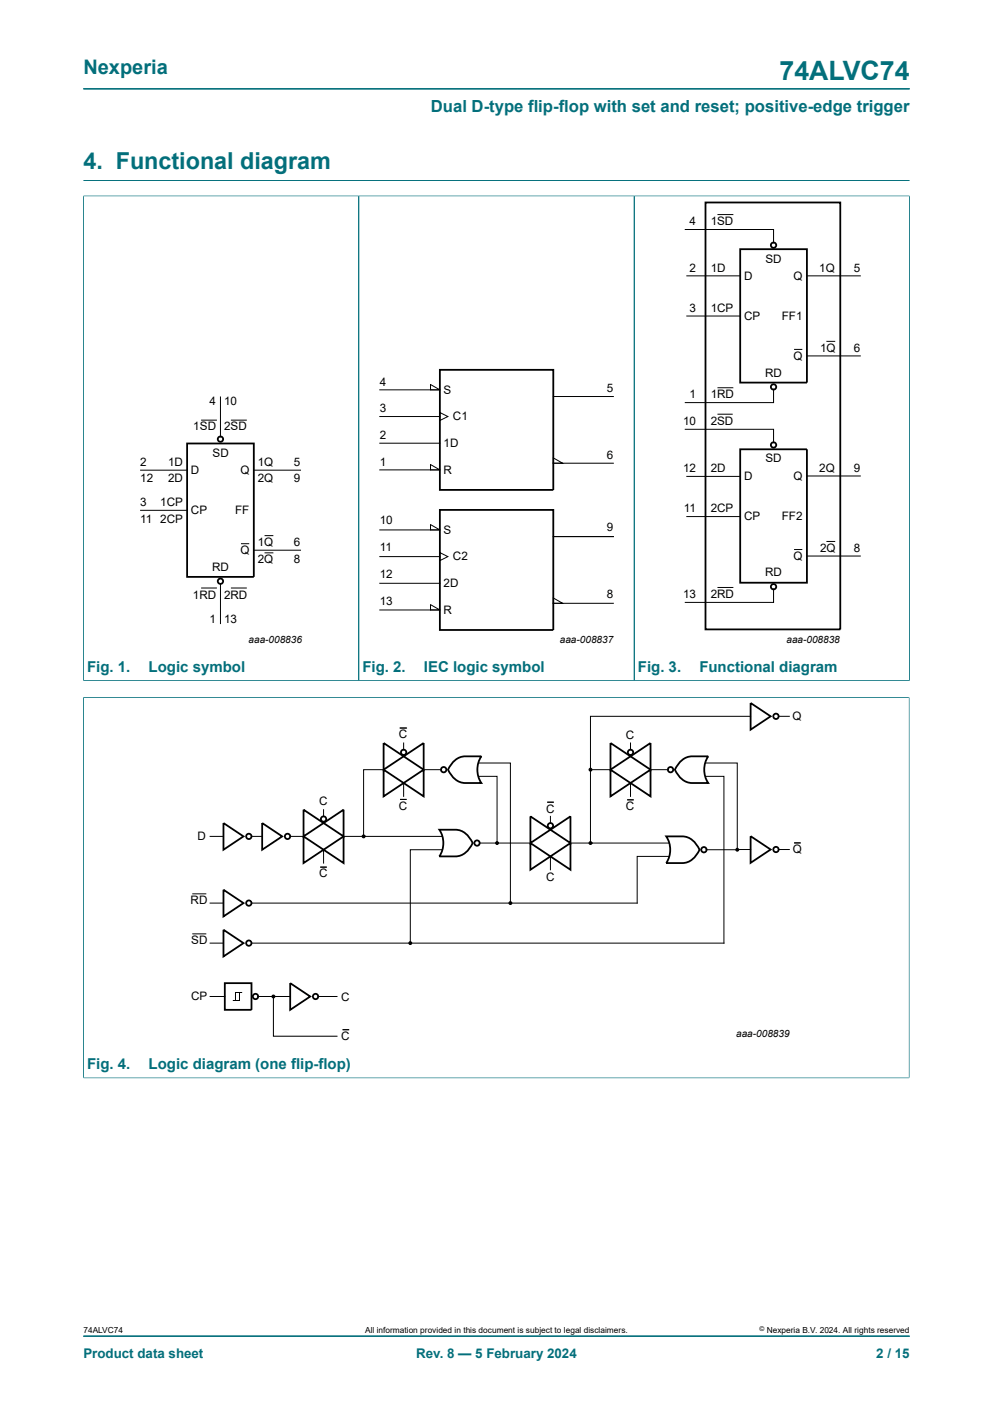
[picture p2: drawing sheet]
<svg xmlns="http://www.w3.org/2000/svg" width="210mm" height="297mm" viewBox="0 0 210 297" stroke-linecap="round" stroke-linejoin="round" font-family="sans-serif">
<defs><g id="words">
<text font-size="5.6" fill="#036f7b" x="164.9" y="16.8">74ALVC74</text>
<text font-size="4.9" fill="#036f7b" x="17.6" y="35.9">4. Functional diagram</text>
<text font-size="4.2" fill="#036f7b" x="17.6" y="15.6">Nexperia</text>
<text font-size="3.5" fill="#036f7b" x="91.1" y="23.7">Dual D-type flip-flop with set and reset; positive-edge trigger</text>
<g font-size="3.2" fill="#036f7b">
<text x="18.4" y="142.1">Fig. 1.</text>
<text x="31.4" y="142.1">Logic symbol</text>
<text x="76.7" y="142.1">Fig. 2.</text>
<text x="89.7" y="142.1">IEC logic symbol</text>
<text x="134.9" y="142.1">Fig. 3.</text>
<text x="147.9" y="142.1">Functional diagram</text>
<text x="18.4" y="226.2">Fig. 4.</text>
<text x="31.4" y="226.2">Logic diagram (one flip-flop)</text>
</g>
<g font-size="2.8" fill="#036f7b">
<text x="17.6" y="287.2">Product data sheet</text>
<text x="88" y="287.2">Rev. 8 — 5 February 2024</text>
<text x="185.3" y="287.2">2 / 15</text>
</g>
<g font-size="2.5">
<text x="145.8" y="47.6">4</text>
<text x="150.3" y="47.6">1SD</text>
<text x="145.8" y="57.5">2</text>
<text x="150.3" y="57.5">1D</text>
<text x="157.4" y="59.2">D</text>
<text x="161.9" y="55.6">SD</text>
<text x="167.8" y="59.2">Q</text>
<text x="173.2" y="57.5">1Q</text>
<text x="180.5" y="57.5">5</text>
<text x="145.8" y="66">3</text>
<text x="150.3" y="66">1CP</text>
<text x="157.4" y="67.6">CP</text>
<text x="165.4" y="67.6">FF1</text>
<text x="167.8" y="76.1">Q</text>
<text x="173.4" y="74.4">1Q</text>
<text x="180.5" y="74.4">6</text>
<text x="80.3" y="81.6">4</text>
<text x="93.8" y="83.3">S</text>
<text x="128.3" y="83">5</text>
<text x="161.8" y="79.7">RD</text>
<text x="44.3" y="85.7">4</text>
<text x="47.4" y="85.7">10</text>
<text x="80.3" y="87.2">3</text>
<text x="95.8" y="88.9">C1</text>
<text x="144.5" y="90">10</text>
<text x="145.8" y="84.3">1</text>
<text x="150.3" y="84.3">1RD</text>
<text x="150.3" y="89.8">2SD</text>
<text x="40.9" y="91.1">1SD</text>
<text x="47.4" y="91.1">2SD</text>
<text x="80.3" y="92.9">2</text>
<text x="93.8" y="94.5">1D</text>
<text x="29.6" y="98.5">2</text>
<text x="35.6" y="98.5">1D</text>
<text x="40.4" y="100.3">D</text>
<text x="44.9" y="96.7">SD</text>
<text x="50.9" y="100.3">Q</text>
<text x="54.5" y="98.5">1Q</text>
<text x="62.2" y="98.5">5</text>
<text x="80.3" y="98.5">1</text>
<text x="93.8" y="100.2">R</text>
<text x="128.3" y="97.1">6</text>
<text x="144.5" y="99.9">12</text>
<text x="150.3" y="99.9">2D</text>
<text x="157.4" y="101.6">D</text>
<text x="161.9" y="97.7">SD</text>
<text x="167.8" y="101.5">Q</text>
<text x="173.2" y="99.8">2Q</text>
<text x="180.5" y="99.8">9</text>
<text x="29.6" y="102">12</text>
<text x="29.6" y="107.1">3</text>
<text x="33.9" y="107.1">1CP</text>
<text x="35.6" y="102">2D</text>
<text x="54.5" y="102">2Q</text>
<text x="62.2" y="102">9</text>
<text x="29.6" y="110.5">11</text>
<text x="33.9" y="110.5">2CP</text>
<text x="40.4" y="108.7">CP</text>
<text x="49.7" y="108.7">FF</text>
<text x="80.3" y="110.9">10</text>
<text x="93.8" y="112.9">S</text>
<text x="128.3" y="112.3">9</text>
<text x="144.6" y="108.4">11</text>
<text x="150.3" y="108.4">2CP</text>
<text x="157.4" y="110">CP</text>
<text x="165.4" y="110">FF2</text>
<text x="50.9" y="117.2">Q</text>
<text x="54.5" y="115.5">1Q</text>
<text x="54.5" y="119.1">2Q</text>
<text x="62.2" y="115.5">6</text>
<text x="62.2" y="119.1">8</text>
<text x="80.3" y="116.6">11</text>
<text x="95.8" y="118.6">C2</text>
<text x="167.8" y="118.4">Q</text>
<text x="173.4" y="116.8">2Q</text>
<text x="180.5" y="116.8">8</text>
<text x="44.9" y="120.8">RD</text>
<text x="80.3" y="122.2">12</text>
<text x="93.8" y="124.2">2D</text>
<text x="161.8" y="121.8">RD</text>
<text x="40.8" y="126.6">1RD</text>
<text x="44.3" y="131.9">1</text>
<text x="47.4" y="126.6">2RD</text>
<text x="47.4" y="131.9">13</text>
<text x="80.3" y="127.9">13</text>
<text x="93.8" y="129.9">R</text>
<text x="128.3" y="126.5">8</text>
<text x="144.5" y="126.5">13</text>
<text x="150.3" y="126.5">2RD</text>
<text x="167.6" y="152.3">Q</text>
<text x="84.3" y="156.2">C</text>
<text x="132.4" y="156.4">C</text>
<text x="67.5" y="170.4">C</text>
<text x="84.3" y="171.3">C</text>
<text x="115.5" y="171.9">C</text>
<text x="132.4" y="171.4">C</text>
<text x="41.8" y="177.7">D</text>
<text x="67.5" y="185.6">C</text>
<text x="167.7" y="180.5">Q</text>
<text x="40.3" y="191.3">RD</text>
<text x="115.5" y="186.4">C</text>
<text x="40.4" y="199.8">SD</text>
<text x="40.4" y="211.6">CP</text>
<text x="72.2" y="211.6">C</text>
<text x="72.2" y="220">C</text>
</g>
<g font-size="2.1">
<text x="52.6" y="136.1">aaa-008836</text>
<text x="118.4" y="136.1">aaa-008837</text>
<text x="166.3" y="136.1">aaa-008838</text>
<text x="155.7" y="219.4">aaa-008839</text>
</g>
<g font-size="1.8">
<text x="17.6" y="282">74ALVC74</text>
<text x="77.2" y="282">All information provided in this document is subject to legal disclaimers.</text>
<text x="162.2" y="282">Nexperia B.V. 2024. All rights reserved</text>
</g>
<text font-size="1.4" x="160.6" y="281.6">©</text>
</g></defs>
<g fill="none" stroke="#036f7b" stroke-width=".21">
<path d="M17.6 18.8h174.8M17.6 38.2h174.8M17.6 41.5h174.8M17.6 41.4v102.7M75.9 41.5v102.5M134.1 41.5v102.5M192.4 41.4v102.7M17.6 147.5h174.7M17.6 144h174.8M17.6 147.4v80.7M192.3 147.4v80.7M17.6 228h174.7"/>
<path d="M17.6 282.6h174.8"/>
</g>
<g fill="none" stroke="#000" stroke-width=".38">
<path d="M149.2 42.8h28.5v90.3h-28.5zM156.5 52.7h14.1v28.2h-14.1zM93 78.2h24v25.4h-24zM39.6 93.8h14.1v28.2h-14.1zM156.5 95h14.1v28.3h-14.1zM93 107.9h24v25.4h-24zM81.1 157.2l4.3 2.8-4.3 2.8zM85.4 160l4.2-2.8v5.6zM129.1 157.2l4.2 2.8-4.2 2.8zM133.3 160l4.3-2.8v5.6zM158.7 148.7l4.3 2.8-4.3 2.9zM47.3 174.1l4.2 2.8-4.2 2.9z"/>
<path d="M55.4 174.1l4.3 2.8-4.3 2.9zM64.2 171.3l4.2 2.8-4.2 2.8zM64.2 176.9l4.2 2.9-4.2 2.8zM68.4 174.1l4.3-2.8v5.6zM68.4 179.8l4.3-2.9v5.7zM81.1 162.8l4.3 2.8-4.3 2.9zM85.4 165.6l4.2-2.8v5.7zM92.9 175.5h3.4a4.1 4.1 0 0 1 3.7 2.8 4.4 4.4 0 0 1-3.7 2.9h-3.4a5.1 5.1 0 0 0 0-5.7zM96 161a3.4 3.4 0 0 1 2.4-1h3.4a5.1 5.1 0 0 0 0 5.6h-3.4a4.1 4.1 0 0 1-3.7-2.8zM112.2 172.7l4.2 2.8-4.2 2.8zM112.2 178.3l4.2 2.9-4.2 2.8zM116.4 175.5l4.2-2.8v5.6z"/>
<path d="M129.1 162.8l4.2 2.8-4.2 2.9zM133.3 165.6l4.3-2.8v5.7zM140.9 176.9h3.4a4.1 4.1 0 0 1 3.6 2.9 4.4 4.4 0 0 1-3.6 2.8h-3.4a5.1 5.1 0 0 0 0-5.7zM144 161a3.4 3.4 0 0 1 2.4-1h3.4a5.1 5.1 0 0 0 0 5.6h-3.4a4.1 4.1 0 0 1-3.7-2.8zM158.7 176.9l4.3 2.8-4.3 2.8zM47.3 188.2l4.2 2.8-4.2 2.9zM47.3 196.7l4.2 2.8-4.2 2.8zM116.4 181.2l4.2-2.9v5.7zM47.5 208h5.7v5.6h-5.7zM61.4 208l4.2 2.8-4.2 2.8z"/>
<circle cx="163.6" cy="51.9" r=".57"/>
<circle cx="46.6" cy="92.9" r=".56"/>
<circle cx="163.6" cy="81.9" r=".57"/>
<circle cx="163.6" cy="94.1" r=".57"/>
<circle cx="46.6" cy="123" r=".56"/>
<circle cx="163.6" cy="124.1" r=".57"/>
<circle cx="85.4" cy="159.1" r=".56"/>
<circle cx="133.3" cy="159.1" r=".56"/>
<circle cx="164.1" cy="151.5" r=".56"/>
<circle cx="52.6" cy="176.9" r=".56"/>
<circle cx="60.8" cy="176.9" r=".56"/>
<circle cx="68.4" cy="173.3" r=".56"/>
<circle cx="93.8" cy="162.8" r=".56"/>
<circle cx="100.9" cy="178.3" r=".56"/>
<circle cx="116.4" cy="174.7" r=".56"/>
<circle cx="141.8" cy="162.8" r=".56"/>
<circle cx="148.9" cy="179.8" r=".56"/>
<circle cx="164.1" cy="179.7" r=".56"/>
<circle cx="52.6" cy="199.5" r=".56"/>
<circle cx="52.6" cy="191" r=".56"/>
<circle cx="54" cy="210.8" r=".56"/>
<circle cx="66.7" cy="210.8" r=".56"/>
</g>
<g fill="none" stroke="#000" stroke-width=".21">
<path d="M144.9 48.5h18.7v2.9M145.2 58.4h11.3M151.8 45.4h3.2M170.6 58.4h11.3M145.2 66.9h11.3M168 73.9h1.6M170.6 75.3h11.3M174.9 72.2h1.6M29.7 99.5h9.9M42.6 88.9h3.2M46.6 84v8.4M48.9 88.9h3.2"/>
<path d="M53.7 99.5h9.9M80.3 82.5h12.7M80.3 99.4h12.7M80.3 88.1h12.7M80.3 93.8h12.7M91 81.3l2 1.2h-2zM91 98.3l2 1.1h-2zM93 87.3l1.7 .8-1.7 .9zM117 96.9l2 1.1h-2zM117 98h12.7M117 83.9h12.7M144.9 90.8h18.7v2.8"/>
<path d="M151.8 82h3.2M151.8 87.6h3M163.6 82.3v2.9h-18.7M29.7 108h9.9M51.1 115h1.5M53.7 116.4h9.9M56.1 113.3h1.6M56.1 116.9h1.6M80.3 112.1h12.7M80.3 117.7h12.7M91 111l2 1.1h-2zM93 116.9l1.7 .8-1.7 .9z"/>
<path d="M117 113.5h12.7M145.2 100.8h11.3M145.2 109.3h11.3M168 116.2h1.6M170.6 100.7h11.3M170.6 117.6h11.3M174.9 114.5h1.6M42.6 124.4h3.2M46.6 123.4v8.5M48.9 124.4h3.2M80.3 129h12.7M80.3 123.4h12.7"/>
<path d="M91 127.9l2 1.1h-2zM117 126.5l2 1.1h-2zM117 127.6h12.7M151.8 124.3h3.2M163.6 124.6v2.8h-18.7M84.6 154h1.4M85.4 157.2v1.4M133.3 157.2v1.4M158.7 151.5h-33.8v11.3M164.7 151.5h2.2M44.4 176.9h2.9M53.2 176.9h2.2"/>
<path d="M61.4 176.9h2.8M68.4 171.3v1.4M68.4 179.8v2.8M72.7 176.9h20.8M81.1 162.8h-4.2v14.1M84.6 169.1h1.4M85.4 165.6v2.9M89.6 162.8h3.7M93.5 179.8h-6.7v19.7M101.2 164.2h3.9v14.1M101.2 161.4h6.7v29.6M101.4 178.3h10.8"/>
<path d="M115.7 169.7h1.4M116.4 172.7v1.4M120.6 178.3h20.9M129.1 162.8h-4.2v15.5M132.6 169.2h1.4M133.3 165.6v2.9M137.6 162.8h3.7M149.2 164.2h3.9v35.3h-99.9M149.2 161.4h6.7v18.4h-6.5M155.9 179.7h2.8M164.7 179.7h2.2M167.9 178.3h1.4"/>
<path d="M40.8 189.1h2.7M40.8 197.5h2.7M44.4 191h2.9M44.4 199.5h2.9M67.7 183.4h1.4M116.4 181.2v2.8M141.5 181.2h-6.7v9.8h-81.6M44.4 210.8h3.1M50.6 209.9v1.7h-1.4M51.2 209.9h-1.4v1.7M54.5 210.8h6.9M57.8 210.8v8.4h13.5"/>
<path d="M67.3 210.8h4M72.5 217.8h1.3"/>
</g>
<g fill="#000">
<path d="M84.6 154h1.4zM84.6 169.1h1.4zM115.7 169.7h1.4zM132.6 169.2h1.4zM167.9 178.3h1.4zM67.7 183.4h1.4zM72.5 217.8h1.3z"/>
<circle cx="76.9" cy="176.9" r=".28"/>
<circle cx="105.1" cy="178.3" r=".28"/>
<circle cx="124.9" cy="178.3" r=".28"/>
<circle cx="124.9" cy="162.8" r=".28"/>
<circle cx="155.9" cy="179.8" r=".28"/>
<circle cx="86.8" cy="199.5" r=".28"/>
<circle cx="107.9" cy="191" r=".28"/>
<circle cx="57.8" cy="210.8" r=".28"/>
</g>
<g fill="none" stroke="#000" stroke-width=".25">
<circle cx="76.9" cy="176.9" r=".28"/>
<circle cx="105.1" cy="178.3" r=".28"/>
<circle cx="124.9" cy="178.3" r=".28"/>
<circle cx="124.9" cy="162.8" r=".28"/>
<circle cx="155.9" cy="179.8" r=".28"/>
<circle cx="86.8" cy="199.5" r=".28"/>
<circle cx="107.9" cy="191" r=".28"/>
<circle cx="57.8" cy="210.8" r=".28"/>
</g>
<use href="#words"/>
</svg>
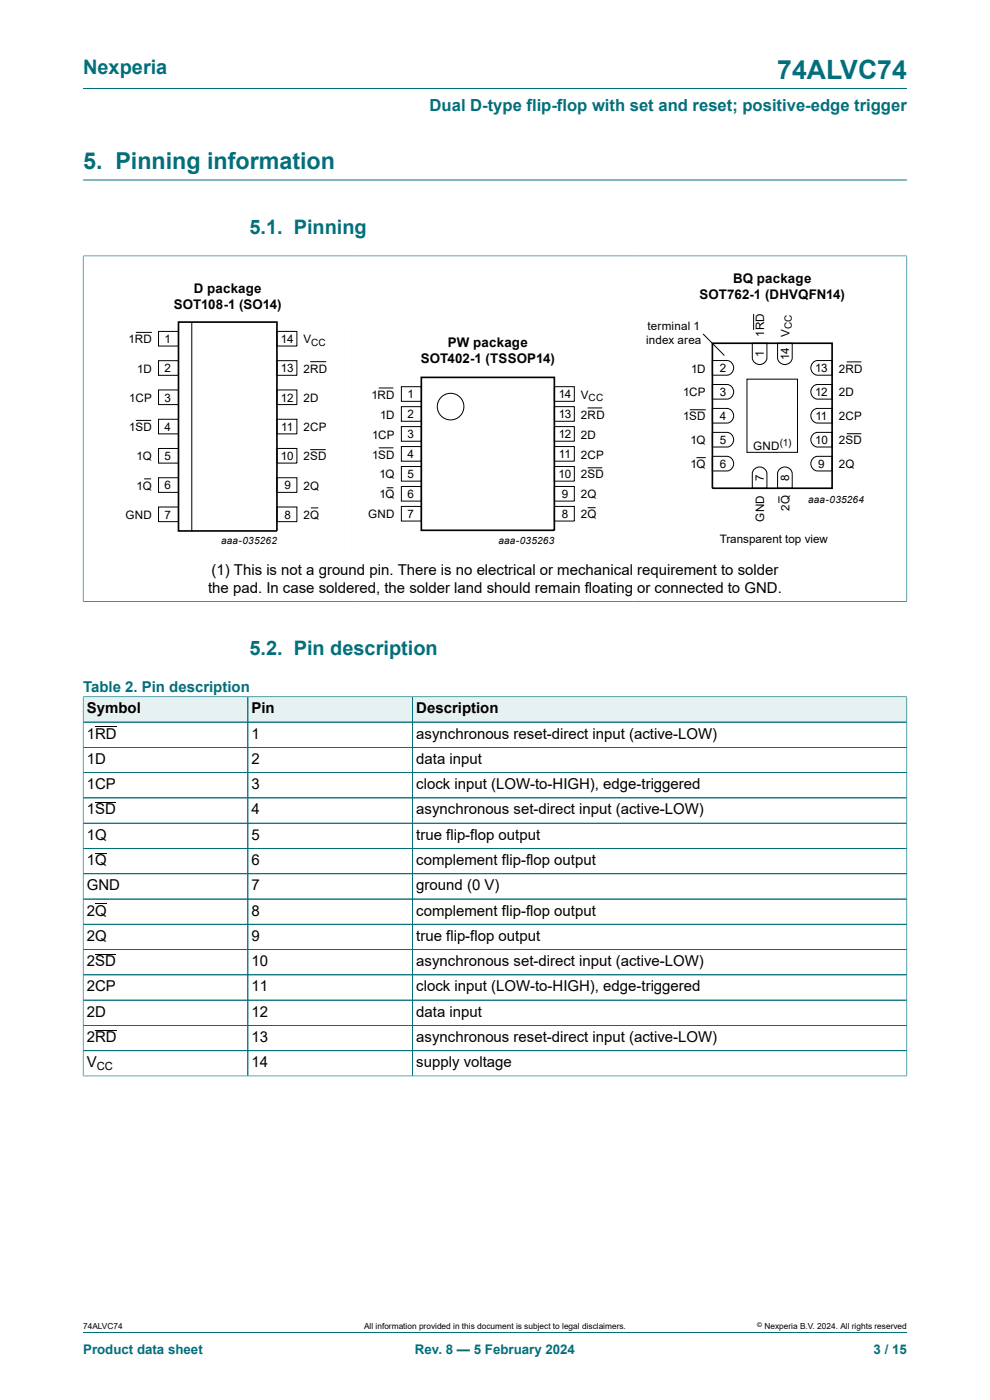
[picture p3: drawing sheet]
<svg xmlns="http://www.w3.org/2000/svg" width="210mm" height="297mm" viewBox="0 0 210 297" stroke-linecap="round" stroke-linejoin="round" font-family="sans-serif">
<defs><g id="words">
<text font-size="5.6" fill="#036f7b" x="164.9" y="16.8">74ALVC74</text>
<text font-size="4.9" fill="#036f7b" x="17.6" y="35.9">5. Pinning information</text>
<g font-size="4.2" fill="#036f7b">
<text x="17.6" y="15.6">Nexperia</text>
<text x="52.9" y="49.7">5.1. Pinning</text>
<text x="52.9" y="139">5.2. Pin description</text>
</g>
<text font-size="3.5" fill="#036f7b" x="91.1" y="23.7">Dual D-type flip-flop with set and reset; positive-edge trigger</text>
<g font-size="3.2">
<text x="44.2" y="125.8">the pad. In case soldered, the solder land should remain floating or connected to GND.</text>
<text x="44.9" y="122">(1) This is not a ground pin. There is no electrical or mechanical requirement to solder</text>
<text x="18.4" y="151.3">Symbol</text>
<text x="53.4" y="151.3">Pin</text>
<text x="88.3" y="151.3">Description</text>
<text x="18.4" y="156.7">1RD</text>
<text x="53.4" y="156.7">1</text>
<text x="88.3" y="156.7">asynchronous reset-direct input (active-LOW)</text>
<text x="18.4" y="162.1">1D</text>
<text x="18.4" y="167.4">1CP</text>
<text x="53.4" y="162.1">2</text>
<text x="53.4" y="167.4">3</text>
<text x="88.3" y="162.1">data input</text>
<text x="88.3" y="167.4">clock input (LOW-to-HIGH), edge-triggered</text>
<text x="18.4" y="172.8">1SD</text>
<text x="53.4" y="172.8">4</text>
<text x="88.3" y="172.8">asynchronous set-direct input (active-LOW)</text>
<text x="18.4" y="178.1">1Q</text>
<text x="53.4" y="178.1">5</text>
<text x="88.3" y="178.1">true flip-flop output</text>
<text x="18.4" y="183.5">1Q</text>
<text x="53.4" y="183.5">6</text>
<text x="88.3" y="183.5">complement flip-flop output</text>
<text x="18.4" y="188.9">GND</text>
<text x="53.4" y="188.9">7</text>
<text x="88.3" y="188.9">ground (0 V)</text>
<text x="18.4" y="194.2">2Q</text>
<text x="53.4" y="194.2">8</text>
<text x="88.3" y="194.2">complement flip-flop output</text>
<text x="18.4" y="199.6">2Q</text>
<text x="53.4" y="199.6">9</text>
<text x="88.3" y="199.6">true flip-flop output</text>
<text x="18.4" y="204.9">2SD</text>
<text x="53.4" y="204.9">10</text>
<text x="88.3" y="204.9">asynchronous set-direct input (active-LOW)</text>
<text x="18.4" y="210.3">2CP</text>
<text x="18.4" y="215.7">2D</text>
<text x="53.4" y="210.3">11</text>
<text x="53.4" y="215.7">12</text>
<text x="88.3" y="210.3">clock input (LOW-to-HIGH), edge-triggered</text>
<text x="88.3" y="215.7">data input</text>
<text x="18.4" y="221">2RD</text>
<text x="53.4" y="221">13</text>
<text x="88.3" y="221">asynchronous reset-direct input (active-LOW)</text>
<text x="18.4" y="226.4">V</text>
<text x="53.4" y="226.4">14</text>
<text x="88.3" y="226.4">supply voltage</text>
</g>
<text font-size="3.2" fill="#036f7b" x="17.6" y="146.7">Table 2. Pin description</text>
<g font-size="2.8">
<text x="36.9" y="65.5">SOT108-1 (SO14)</text>
<text x="41.1" y="62.1">D package</text>
<text x="148.4" y="63.5">SOT762-1 (DHVQFN14)</text>
<text x="155.5" y="60.1">BQ package</text>
<text x="89.2" y="76.9">SOT402-1 (TSSOP14)</text>
<text x="95" y="73.6">PW package</text>
</g>
<g font-size="2.8" fill="#036f7b">
<text x="17.6" y="287.2">Product data sheet</text>
<text x="88" y="287.2">Rev. 8 — 5 February 2024</text>
<text x="185.3" y="287.2">3 / 15</text>
</g>
<g font-size="2.5">
<text x="137.4" y="70">terminal 1</text>
<text x="162.1" y="71.4" transform="rotate(-90 162.1 71.4)">1RD</text>
<text x="167.5" y="71.4" transform="rotate(-90 167.5 71.4)">V</text>
<text x="27.3" y="72.8">1RD</text>
<text x="34.9" y="72.8">1</text>
<text x="59.6" y="72.8">14</text>
<text x="64.4" y="72.8">V</text>
<text x="137.1" y="73">index area</text>
<text x="162" y="75.8" transform="rotate(-90 162 75.8)">1</text>
<text x="167.4" y="76.4" transform="rotate(-90 167.4 76.4)">14</text>
<text x="29.1" y="79.1">1D</text>
<text x="34.9" y="79">2</text>
<text x="59.6" y="79">13</text>
<text x="64.4" y="79.1">2RD</text>
<text x="146.6" y="79">1D</text>
<text x="152.7" y="79">2</text>
<text x="172.9" y="79">13</text>
<text x="177.9" y="79">2RD</text>
<text x="27.4" y="85.3">1CP</text>
<text x="34.9" y="85.2">3</text>
<text x="59.6" y="85.2">12</text>
<text x="64.4" y="85.3">2D</text>
<text x="78.8" y="84.6">1RD</text>
<text x="80.6" y="88.8">1D</text>
<text x="86.4" y="84.5">1</text>
<text x="86.4" y="88.7">2</text>
<text x="118.5" y="84.5">14</text>
<text x="118.5" y="88.7">13</text>
<text x="123.2" y="84.6">V</text>
<text x="123.2" y="88.8">2RD</text>
<text x="144.9" y="89.2">1SD</text>
<text x="144.9" y="84.1">1CP</text>
<text x="152.7" y="89.1">4</text>
<text x="152.7" y="84">3</text>
<text x="172.9" y="84">12</text>
<text x="173" y="89.1">11</text>
<text x="177.9" y="89.2">2CP</text>
<text x="177.9" y="84.1">2D</text>
<text x="27.4" y="91.5">1SD</text>
<text x="34.9" y="91.4">4</text>
<text x="59.6" y="91.4">11</text>
<text x="64.4" y="91.5">2CP</text>
<text x="78.9" y="93">1CP</text>
<text x="86.4" y="93">3</text>
<text x="118.5" y="93">12</text>
<text x="123.2" y="93">2D</text>
<text x="146.5" y="94.3">1Q</text>
<text x="152.7" y="94.2">5</text>
<text x="159.8" y="95.4">GND</text>
<text x="172.9" y="94.2">10</text>
<text x="177.9" y="94.3">2SD</text>
<text x="29" y="97.7">1Q</text>
<text x="34.9" y="97.6">5</text>
<text x="59.6" y="97.6">10</text>
<text x="64.4" y="97.7">2SD</text>
<text x="78.9" y="97.3">1SD</text>
<text x="80.5" y="101.5">1Q</text>
<text x="86.4" y="97.2">4</text>
<text x="86.4" y="101.4">5</text>
<text x="118.5" y="101.4">10</text>
<text x="118.6" y="97.2">11</text>
<text x="123.2" y="97.3">2CP</text>
<text x="123.2" y="101.5">2SD</text>
<text x="146.5" y="99.3">1Q</text>
<text x="152.7" y="99.3">6</text>
<text x="173.6" y="99.3">9</text>
<text x="177.9" y="99.3">2Q</text>
<text x="29" y="103.9">1Q</text>
<text x="34.9" y="103.8">6</text>
<text x="60.3" y="103.8">9</text>
<text x="64.4" y="103.9">2Q</text>
<text x="80.5" y="105.7">1Q</text>
<text x="86.4" y="105.7">6</text>
<text x="119.2" y="105.7">9</text>
<text x="123.2" y="105.7">2Q</text>
<text x="162" y="102" transform="rotate(-90 162 102)">7</text>
<text x="167.4" y="102" transform="rotate(-90 167.4 102)">8</text>
<text x="26.6" y="110.1">GND</text>
<text x="34.9" y="110">7</text>
<text x="60.3" y="110">8</text>
<text x="64.4" y="110.1">2Q</text>
<text x="78.1" y="110">GND</text>
<text x="86.4" y="109.9">7</text>
<text x="119.2" y="110">8</text>
<text x="123.2" y="110">2Q</text>
<text x="162.1" y="110.7" transform="rotate(-90 162.1 110.7)">GND</text>
<text x="167.5" y="108.4" transform="rotate(-90 167.5 108.4)">2Q</text>
<text x="152.7" y="115.1">Transparent top view</text>
</g>
<text font-size="2.4" x="20.5" y="227">CC</text>
<g font-size="2.1">
<text x="168" y="69.8" transform="rotate(-90 168 69.8)">CC</text>
<text x="66" y="73.3">CC</text>
<text x="124.9" y="85.1">CC</text>
<text x="165.4" y="94.7">(1)</text>
<text x="171.4" y="106.7">aaa-035264</text>
<text x="46.9" y="115.5">aaa-035262</text>
<text x="105.7" y="115.3">aaa-035263</text>
</g>
<g font-size="1.8">
<text x="17.6" y="282">74ALVC74</text>
<text x="77.2" y="282">All information provided in this document is subject to legal disclaimers.</text>
<text x="162.2" y="282">Nexperia B.V. 2024. All rights reserved</text>
</g>
<text font-size="1.4" x="160.6" y="281.6">©</text>
</g></defs>
<path d="M17.6 18.8h174.8M17.6 38.2h174.8M17.6 54.3h174.8M17.6 54.2v73.5M192.4 54.2v73.5M17.6 127.6h174.8" fill="none" stroke="#036f7b" stroke-width=".21"/>
<g fill="none" stroke="#000" stroke-width=".21">
<path d="M28.8 70.5h3.4M33.6 70.3h4.3v3.1h-4.3zM33.6 76.5h4.3v3.1h-4.3zM40.7 68.3v44.4M58.7 70.3h4.3v3.1h-4.3zM58.7 76.5h4.3v3.1h-4.3zM65.8 76.7h3.4M149.1 70.8l4.6 4.6M151.1 76.5h3.1a1.56 1.56 0 0 1 1.4 1.5 1.56 1.56 0 0 1-1.4 1.6h-3.1zM159.6 72.8h3.1v3.1a1.56 1.56 0 0 1-1.6 1.4 1.56 1.56 0 0 1-1.5-1.4zM159.9 66.6v3.4M164.9 72.8h3.1v3.1a1.56 1.56 0 0 1-1.5 1.4 1.56 1.56 0 0 1-1.6-1.4z"/>
<path d="M172.6 76.8l.8-.3h3.1v3.1h-3.1a1.57 1.57 0 0 1-1.3-1.1 1.57 1.57 0 0 1 .5-1.7zM179.6 76.8h3.1M28.8 89.2h3.2M33.6 82.7h4.3v3.1h-4.3zM33.6 88.9h4.3v3.1h-4.3zM33.6 95.1h4.3v3.1h-4.3zM58.7 95.1h4.3v3.1h-4.3zM58.7 82.7h4.3v3.1h-4.3zM58.7 88.9h4.3v3.1h-4.3zM65.8 95.4h3.3M80.3 82.3h3.1M80.3 95h3.1"/>
<path d="M85.1 82h4.3v3.1h-4.3zM85.1 86.3h4.3v3.1h-4.3zM85.1 90.5h4.3v3.1h-4.3zM85.1 94.7h4.3v3.1h-4.3zM85.1 99h4.3v3.1h-4.3zM117.6 99h4.2v3.1h-4.2zM117.6 90.5h4.2v3.1h-4.2zM117.6 94.7h4.2v3.1h-4.2zM117.6 82h4.2v3.1h-4.2zM117.6 86.3h4.2v3.1h-4.2zM124.6 86.5h3.2M124.6 99.2h3.2"/>
<path d="M146.3 86.9h3.4M147.7 97.1h2M151.1 96.8h3.1a1.56 1.56 0 0 1 1.4 1.6 1.56 1.56 0 0 1-1.4 1.5h-3.1zM151.1 91.7h3.1a1.56 1.56 0 0 1 1.4 1.6 1.56 1.56 0 0 1-1.4 1.5h-3.1zM151.1 86.6h3.1a1.56 1.56 0 0 1 1.4 1.6 1.56 1.56 0 0 1-1.4 1.6h-3.1zM151.1 81.6h3.1a1.56 1.56 0 0 1 1.4 1.5 1.56 1.56 0 0 1-1.4 1.6h-3.1zM158.4 80.4h10.8v15.6h-10.8zM159.9 99.6a1.57 1.57 0 0 1 1.7-.5 1.57 1.57 0 0 1 1.1 1.4v3.1h-3.1v-3.1zM165.3 99.6a1.57 1.57 0 0 1 1.6-.5 1.57 1.57 0 0 1 1.1 1.4v3.1h-3.1v-3.1zM172.6 97.1l.8-.3h3.1v3.1h-3.1a1.57 1.57 0 0 1-1.3-1.1 1.57 1.57 0 0 1 .5-1.7zM172.6 92l.8-.3h3.1v3.1h-3.1a1.57 1.57 0 0 1-1.3-1.1 1.57 1.57 0 0 1 .5-1.7zM172.6 87l.8-.4h3.1v3.2h-3.1a1.57 1.57 0 0 1-1.3-1.2 1.57 1.57 0 0 1 .5-1.6z"/>
<path d="M172.6 81.9l.8-.3h3.1v3.1h-3.1a1.57 1.57 0 0 1-1.3-1.1 1.57 1.57 0 0 1 .5-1.7zM179.6 92h3.1M30.6 101.6h1.4M33.6 101.4h4.3v3.1h-4.3zM33.6 107.6h4.3v3.1h-4.3zM58.7 107.6h4.3v3.1h-4.3zM58.7 101.4h4.3v3.1h-4.3zM65.9 107.7h1.6M82 103.5h1.4M85.1 103.2h4.3v3.1h-4.3zM85.1 107.4h4.3v3.1h-4.3zM117.6 107.4h4.2v3.1h-4.2z"/>
<path d="M117.6 103.2h4.2v3.1h-4.2zM124.6 107.7h1.7M165.2 105.3v1.4"/>
<circle cx="95.6" cy="86.3" r="2.82"/>
</g>
<path d="M37.9 68.3h20.8v44.3h-20.8zM151.1 72.8h25.4v30.8h-25.4zM89.4 80.1h28.2v32.4h-28.2z" fill="none" stroke="#000" stroke-width=".35"/>
<path d="M23 57.9h50.1v60h-50.1zM133.4 55.8h53.6v62.1h-53.6zM74.4 69.2h57.5v48.7h-57.5z" fill="none" stroke="#fefefe" stroke-width=".21"/>
<path d="M17.7 147.9h34.8v5.2h-34.8z" fill="#e6f1f2"/>
<path d="M17.6 147.8v5.4h35v-5.4h-35" fill="none" stroke="#036f7b" stroke-width=".21"/>
<path d="M52.7 147.9h34.8v5.2h-34.8z" fill="#e6f1f2"/>
<path d="M52.6 147.8h34.9v5.4h-34.9z" fill="none" stroke="#036f7b" stroke-width=".21"/>
<path d="M87.6 147.9h104.7v5.2h-104.7z" fill="#e6f1f2"/>
<g fill="none" stroke="#036f7b" stroke-width=".21">
<path d="M17.6 158.5h174.8M17.6 153.2h174.8M17.6 147.9v80.4M17.7 147.8h174.7M52.6 147.9v80.4M87.5 147.8v80.5M192.4 147.8v80.5M17.6 163.9h174.8M17.6 169.3h174.8M17.6 174.6h174.8M17.6 180h174.8M17.6 185.4h174.8"/>
<path d="M17.6 190.7h174.8M17.6 196.1h174.8M17.6 201.4h174.8M17.6 206.8h174.8M17.6 212.2h174.8M17.6 217.5h174.8M17.6 228.3h174.8M17.6 222.9h174.8M17.6 282.6h174.8"/>
</g>
<path d="M20.2 154.2h4.6M20.2 170.3h4.4M20.2 181h2.4M20.2 191.7h2.4M20.2 202.5h4.4M20.2 218.5h4.6" fill="none" stroke="#000" stroke-width=".21"/>
<use href="#words"/>
</svg>
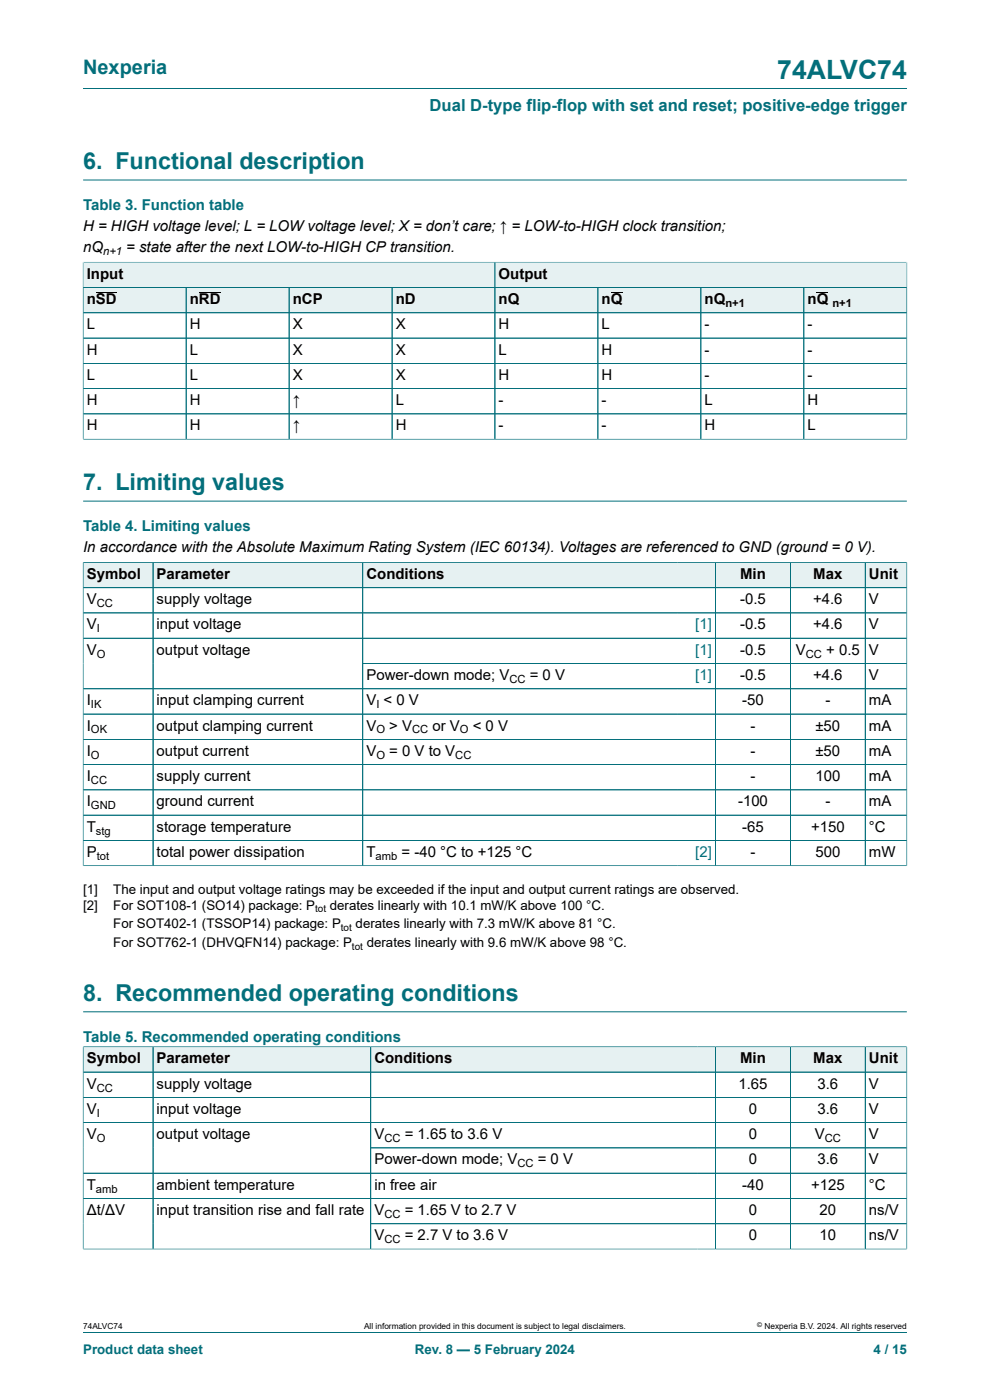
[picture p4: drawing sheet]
<svg xmlns="http://www.w3.org/2000/svg" width="210mm" height="297mm" viewBox="0 0 210 297" stroke-linecap="round" stroke-linejoin="round" font-family="sans-serif">
<defs><g id="words">
<text font-size="5.6" fill="#036f7b" x="164.9" y="16.8">74ALVC74</text>
<g font-size="4.9" fill="#036f7b">
<text x="17.6" y="35.9">6. Functional description</text>
<text x="17.6" y="104">7. Limiting values</text>
<text x="17.6" y="212.3">8. Recommended operating conditions</text>
</g>
<text font-size="4.2" fill="#036f7b" x="17.6" y="15.6">Nexperia</text>
<text font-size="3.5" fill="#036f7b" x="91.1" y="23.7">Dual D-type flip-flop with set and reset; positive-edge trigger</text>
<g font-size="3.2" fill="#036f7b">
<text x="17.6" y="44.5">Table 3. Function table</text>
<text x="17.6" y="112.7">Table 4. Limiting values</text>
<text x="17.6" y="221">Table 5. Recommended operating conditions</text>
</g>
<g font-size="3.2">
<text x="17.6" y="49.1">H = HIGH voltage level; L = LOW voltage level; X = don’t care; ↑ = LOW-to-HIGH clock transition;</text>
<text x="17.6" y="53.5">nQ</text>
<text x="26.8" y="53.5">= state after the next LOW-to-HIGH CP transition.</text>
<text x="18.4" y="59.1">Input</text>
<text x="105.8" y="59.1">Output</text>
<text x="18.4" y="64.5">nSD</text>
<text x="40.3" y="64.5">nRD</text>
<text x="62.1" y="64.5">nCP</text>
<text x="83.9" y="64.5">nD</text>
<text x="105.8" y="64.5">nQ</text>
<text x="127.6" y="64.5">nQ</text>
<text x="149.5" y="64.5">nQ</text>
<text x="171.3" y="64.5">nQ</text>
<text x="18.4" y="69.9">L</text>
<text x="40.3" y="69.9">H</text>
<text x="62.1" y="69.9">X</text>
<text x="83.9" y="69.9">X</text>
<text x="105.8" y="69.9">H</text>
<text x="127.6" y="69.9">L</text>
<text x="149.5" y="69.9">-</text>
<text x="171.3" y="69.9">-</text>
<text x="18.4" y="75.2">H</text>
<text x="40.3" y="75.2">L</text>
<text x="62.1" y="75.2">X</text>
<text x="83.9" y="75.2">X</text>
<text x="105.8" y="75.2">L</text>
<text x="127.6" y="75.2">H</text>
<text x="149.5" y="75.2">-</text>
<text x="171.3" y="75.2">-</text>
<text x="18.4" y="80.6">L</text>
<text x="40.3" y="80.6">L</text>
<text x="62.1" y="80.6">X</text>
<text x="83.9" y="80.6">X</text>
<text x="105.8" y="80.6">H</text>
<text x="127.6" y="80.6">H</text>
<text x="149.5" y="80.6">-</text>
<text x="171.3" y="80.6">-</text>
<text x="18.4" y="85.9">H</text>
<text x="40.3" y="85.9">H</text>
<text x="62.1" y="85.9">↑</text>
<text x="83.9" y="85.9">L</text>
<text x="105.8" y="85.9">-</text>
<text x="127.6" y="85.9">-</text>
<text x="149.5" y="85.9">L</text>
<text x="171.3" y="85.9">H</text>
<text x="18.4" y="91.3">H</text>
<text x="40.3" y="91.3">H</text>
<text x="62.1" y="91.3">↑</text>
<text x="83.9" y="91.3">H</text>
<text x="105.8" y="91.3">-</text>
<text x="127.6" y="91.3">-</text>
<text x="149.5" y="91.3">H</text>
<text x="171.3" y="91.3">L</text>
<text x="17.6" y="117.2">In accordance with the Absolute Maximum Rating System (IEC 60134). Voltages are referenced to GND (ground = 0 V).</text>
<text x="18.4" y="122.8">Symbol</text>
<text x="33.2" y="122.8">Parameter</text>
<text x="77.7" y="122.8">Conditions</text>
<text x="157" y="122.8">Min</text>
<text x="172.5" y="122.8">Max</text>
<text x="184.3" y="122.8">Unit</text>
<text x="18.4" y="128.2">V</text>
<text x="33.2" y="128.2">supply voltage</text>
<text x="157" y="128.2">-0.5</text>
<text x="172.5" y="128.2">+4.6</text>
<text x="184.3" y="128.2">V</text>
<text x="18.4" y="133.5">V</text>
<text x="33.2" y="133.5">input voltage</text>
<text x="157" y="133.5">-0.5</text>
<text x="172.5" y="133.5">+4.6</text>
<text x="184.3" y="133.5">V</text>
<text x="18.4" y="138.9">V</text>
<text x="33.2" y="138.9">output voltage</text>
<text x="157" y="138.9">-0.5</text>
<text x="168.8" y="138.9">V</text>
<text x="175.2" y="138.9">+ 0.5</text>
<text x="184.3" y="138.9">V</text>
<text x="18.4" y="149.6">I</text>
<text x="33.2" y="149.6">input clamping current</text>
<text x="77.7" y="144.3">Power-down mode; V</text>
<text x="77.7" y="149.6">V &lt; 0 V</text>
<text x="112.4" y="144.3">= 0 V</text>
<text x="157" y="144.3">-0.5</text>
<text x="157.4" y="149.6">-50</text>
<text x="172.5" y="144.3">+4.6</text>
<text x="175.1" y="149.6">-</text>
<text x="184.3" y="144.3">V</text>
<text x="184.3" y="149.6">mA</text>
<text x="18.4" y="155">I</text>
<text x="33.2" y="155">output clamping current</text>
<text x="77.7" y="155">V</text>
<text x="82.6" y="155">&gt; V</text>
<text x="91.7" y="155">or V</text>
<text x="100.3" y="155">&lt; 0 V</text>
<text x="159.2" y="155">-</text>
<text x="173" y="155">±50</text>
<text x="184.3" y="155">mA</text>
<text x="18.4" y="160.3">I</text>
<text x="33.2" y="160.3">output current</text>
<text x="77.7" y="160.3">V</text>
<text x="82.6" y="160.3">= 0 V to V</text>
<text x="159.2" y="160.3">-</text>
<text x="173" y="160.3">±50</text>
<text x="184.3" y="160.3">mA</text>
<text x="18.4" y="165.7">I</text>
<text x="33.2" y="165.7">supply current</text>
<text x="159.2" y="165.7">-</text>
<text x="173" y="165.7">100</text>
<text x="184.3" y="165.7">mA</text>
<text x="18.4" y="171.1">I</text>
<text x="33.2" y="171.1">ground current</text>
<text x="156.6" y="171.1">-100</text>
<text x="175.1" y="171.1">-</text>
<text x="184.3" y="171.1">mA</text>
<text x="18.4" y="176.4">T</text>
<text x="33.2" y="176.4">storage temperature</text>
<text x="157.4" y="176.4">-65</text>
<text x="172" y="176.4">+150</text>
<text x="184.3" y="176.4">°C</text>
<text x="18.4" y="181.8">P</text>
<text x="33.2" y="181.8">total power dissipation</text>
<text x="77.7" y="181.8">T</text>
<text x="85.2" y="181.8">= -40 °C to +125 °C</text>
<text x="159.2" y="181.8">-</text>
<text x="173" y="181.8">500</text>
<text x="184.3" y="181.8">mW</text>
<text x="18.4" y="225.6">Symbol</text>
<text x="33.2" y="225.6">Parameter</text>
<text x="79.4" y="225.6">Conditions</text>
<text x="157" y="225.6">Min</text>
<text x="172.5" y="225.6">Max</text>
<text x="184.3" y="225.6">Unit</text>
<text x="18.4" y="230.9">V</text>
<text x="33.2" y="230.9">supply voltage</text>
<text x="156.6" y="230.9">1.65</text>
<text x="173.4" y="230.9">3.6</text>
<text x="184.3" y="230.9">V</text>
<text x="18.4" y="236.3">V</text>
<text x="33.2" y="236.3">input voltage</text>
<text x="158.8" y="236.3">0</text>
<text x="173.4" y="236.3">3.6</text>
<text x="184.3" y="236.3">V</text>
<text x="18.4" y="241.7">V</text>
<text x="33.2" y="241.7">output voltage</text>
<text x="79.4" y="241.7">V</text>
<text x="85.8" y="241.7">= 1.65 to 3.6 V</text>
<text x="158.8" y="241.7">0</text>
<text x="172.8" y="241.7">V</text>
<text x="184.3" y="241.7">V</text>
<text x="79.4" y="247">Power-down mode; V</text>
<text x="114.1" y="247">= 0 V</text>
<text x="158.8" y="247">0</text>
<text x="173.4" y="247">3.6</text>
<text x="184.3" y="247">V</text>
<text x="18.4" y="252.4">T</text>
<text x="18.4" y="257.8">Δt/ΔV</text>
<text x="33.2" y="252.4">ambient temperature</text>
<text x="33.2" y="257.8">input transition rise and fall rate</text>
<text x="79.4" y="252.4">in free air</text>
<text x="79.4" y="257.8">V</text>
<text x="85.8" y="257.8">= 1.65 V to 2.7 V</text>
<text x="157.4" y="252.4">-40</text>
<text x="158.8" y="257.8">0</text>
<text x="172" y="252.4">+125</text>
<text x="173.8" y="257.8">20</text>
<text x="184.3" y="252.4">°C</text>
<text x="184.3" y="257.8">ns/V</text>
<text x="79.4" y="263.1">V</text>
<text x="85.8" y="263.1">= 2.7 V to 3.6 V</text>
<text x="158.8" y="263.1">0</text>
<text x="173.8" y="263.1">10</text>
<text x="184.3" y="263.1">ns/V</text>
</g>
<g font-size="3.2" fill="#00f">
<text x="147.5" y="133.5">[1]</text>
<text x="147.5" y="138.9">[1]</text>
<text x="147.5" y="144.3">[1]</text>
<text x="147.5" y="181.8">[2]</text>
</g>
<g font-size="2.8">
<text x="17.6" y="189.6">[1]</text>
<text x="24" y="189.6">The input and output voltage ratings may be exceeded if the input and output current ratings are observed.</text>
<text x="17.6" y="193">[2]</text>
<text x="24" y="193">For SOT108-1 (SO14) package: P</text>
<text x="24" y="196.9">For SOT402-1 (TSSOP14) package: P</text>
<text x="70" y="193">derates linearly with 10.1 mW/K above 100 °C.</text>
<text x="75.4" y="196.9">derates linearly with 7.3 mW/K above 81 °C.</text>
<text x="24" y="200.9">For SOT762-1 (DHVQFN14) package: P</text>
<text x="77.8" y="200.9">derates linearly with 9.6 mW/K above 98 °C.</text>
</g>
<g font-size="2.8" fill="#036f7b">
<text x="17.6" y="287.2">Product data sheet</text>
<text x="88" y="287.2">Rev. 8 — 5 February 2024</text>
<text x="185.3" y="287.2">4 / 15</text>
</g>
<g font-size="2.4">
<text x="21.9" y="54.1">n+1</text>
<text x="153.9" y="65.1">n+1</text>
<text x="176.6" y="65.1">n+1</text>
<text x="20.5" y="128.8">CC</text>
<text x="20.5" y="134.2">I</text>
<text x="20.5" y="139.5">O</text>
<text x="170.9" y="139.5">CC</text>
<text x="108.1" y="144.9">CC</text>
<text x="19.3" y="150.2">IK</text>
<text x="19.3" y="155.6">OK</text>
<text x="79.8" y="150.2">I</text>
<text x="79.8" y="155.6">O</text>
<text x="87.4" y="155.6">CC</text>
<text x="97.5" y="155.6">O</text>
<text x="19.3" y="161">O</text>
<text x="79.8" y="161">O</text>
<text x="96.6" y="161">CC</text>
<text x="19.3" y="166.3">CC</text>
<text x="19.3" y="171.7">GND</text>
<text x="20.4" y="177.1">stg</text>
<text x="20.5" y="182.4">tot</text>
<text x="79.7" y="182.4">amb</text>
<text x="20.5" y="231.6">CC</text>
<text x="20.5" y="236.9">I</text>
<text x="20.5" y="242.3">O</text>
<text x="81.5" y="242.3">CC</text>
<text x="174.9" y="242.3">CC</text>
<text x="109.7" y="247.6">CC</text>
<text x="20.4" y="253">amb</text>
<text x="81.5" y="258.4">CC</text>
<text x="81.5" y="263.7">CC</text>
</g>
<g font-size="2.1">
<text x="66.8" y="193.5">tot</text>
<text x="72.3" y="197.5">tot</text>
<text x="74.7" y="201.4">tot</text>
</g>
<g font-size="1.8">
<text x="17.6" y="282">74ALVC74</text>
<text x="77.2" y="282">All information provided in this document is subject to legal disclaimers.</text>
<text x="162.2" y="282">Nexperia B.V. 2024. All rights reserved</text>
</g>
<text font-size="1.4" x="160.6" y="281.6">©</text>
</g></defs>
<path d="M17.6 18.8h174.8M17.6 38.2h174.8M17.6 55.6v5.4h87.4v-5.4h-87.4" fill="none" stroke="#036f7b" stroke-width=".21"/>
<path d="M17.7 55.7h87.2v5.2h-87.2z" fill="#e6f1f2"/>
<path d="M192.4 55.6v5.4h-87.4v-5.4h87.4" fill="none" stroke="#036f7b" stroke-width=".21"/>
<g fill="#e6f1f2">
<path d="M105.1 55.7h87.2v5.2h-87.2z"/>
<path d="M17.7 61.1h21.7v5.2h-21.7z"/>
</g>
<path d="M17.6 61h21.9v5.4h-21.9z" fill="none" stroke="#036f7b" stroke-width=".21"/>
<path d="M20.4 62h4.4" fill="none" stroke="#000" stroke-width=".21"/>
<path d="M39.5 61.1h21.7v5.2h-21.7z" fill="#e6f1f2"/>
<path d="M39.5 61h21.8v5.4h-21.8z" fill="none" stroke="#036f7b" stroke-width=".21"/>
<path d="M42.2 62h4.6" fill="none" stroke="#000" stroke-width=".21"/>
<path d="M61.4 61.1h21.7v5.2h-21.7z" fill="#e6f1f2"/>
<path d="M61.3 61h21.9v5.4h-21.9z" fill="none" stroke="#036f7b" stroke-width=".21"/>
<path d="M83.2 61.1h21.7v5.2h-21.7z" fill="#e6f1f2"/>
<path d="M83.2 61h21.8v5.4h-21.8z" fill="none" stroke="#036f7b" stroke-width=".21"/>
<path d="M105.1 61.1h21.7v5.2h-21.7z" fill="#e6f1f2"/>
<path d="M105 61h21.8v5.4h-21.8z" fill="none" stroke="#036f7b" stroke-width=".21"/>
<path d="M126.9 61.1h21.7v5.2h-21.7z" fill="#e6f1f2"/>
<path d="M126.8 61h21.9v5.4h-21.9z" fill="none" stroke="#036f7b" stroke-width=".21"/>
<path d="M129.6 62h2.4" fill="none" stroke="#000" stroke-width=".21"/>
<path d="M148.8 61.1h21.6v5.2h-21.6z" fill="#e6f1f2"/>
<path d="M148.7 61h21.8v5.4h-21.8z" fill="none" stroke="#036f7b" stroke-width=".21"/>
<path d="M170.6 61.1h21.7v5.2h-21.7z" fill="#e6f1f2"/>
<g fill="none" stroke="#036f7b" stroke-width=".21">
<path d="M17.6 55.7v37.5M17.7 55.6h174.6M105 55.7v37.5M192.4 55.7v37.5M17.6 66.4h174.8M17.6 71.7h174.8M17.6 77.1h174.8M17.7 61h174.7M39.5 61.1v32.1M61.3 61.1v32.1M83.2 61.1v32.1M126.8 61.1v32.1"/>
<path d="M148.7 61.1v32.1M170.5 61v32.2M17.6 93.2h174.8M17.6 82.4h174.8M17.6 87.8h174.8M17.6 106.3h174.8"/>
</g>
<path d="M173.2 62h2.5" fill="none" stroke="#000" stroke-width=".21"/>
<path d="M17.7 119.4h14.7v5.2h-14.7z" fill="#e6f1f2"/>
<path d="M17.6 119.2v5.5h14.9v-5.4h-14.9" fill="none" stroke="#036f7b" stroke-width=".21"/>
<path d="M32.5 119.4h44.4v5.2h-44.4z" fill="#e6f1f2"/>
<path d="M32.5 119.3h44.4v5.4h-44.4z" fill="none" stroke="#036f7b" stroke-width=".21"/>
<path d="M77 119.4h66.7v5.2h-66.7z" fill="#e6f1f2"/>
<path d="M143.7 119.3h-66.8v5.4h66.8" fill="none" stroke="#036f7b" stroke-width=".21"/>
<path d="M143.7 119.4h8v5.2h-8z" fill="#e6f1f2"/>
<path d="M143.7 119.3h8.1v5.4h-8.1" fill="none" stroke="#036f7b" stroke-width=".21"/>
<path d="M151.9 119.4h15.7v5.2h-15.7z" fill="#e6f1f2"/>
<path d="M151.8 119.3h15.9v5.4h-15.9z" fill="none" stroke="#036f7b" stroke-width=".21"/>
<path d="M167.7 119.4h15.8v5.2h-15.8z" fill="#e6f1f2"/>
<path d="M167.7 119.3h15.8v5.4h-15.8z" fill="none" stroke="#036f7b" stroke-width=".21"/>
<path d="M183.6 119.4h8.7v5.2h-8.7z" fill="#e6f1f2"/>
<g fill="none" stroke="#036f7b" stroke-width=".21">
<path d="M17.6 119.4v64.3M17.7 119.3h174.7M32.5 119.4v64.3M76.9 119.4v64.3M151.8 119.4v64.3M167.7 119.4v64.3M183.5 119.3v64.4M192.4 119.2v64.5M17.6 130h174.8M192.4 124.7h-174.8M192.4 135.4h-174.8M17.6 156.8h174.8"/>
<path d="M76.9 140.8h115.5M192.4 146.1h-174.8M192.4 151.5h-174.8M17.6 167.6h174.8M192.4 162.2h-174.8M192.4 172.9h-174.8M192.4 178.3h-174.8M17.6 183.7h174.8M17.6 214.6h174.8"/>
</g>
<path d="M17.7 222.1h14.7v5.3h-14.7z" fill="#e6f1f2"/>
<path d="M17.6 222v5.4h14.9v-5.3h-14.9" fill="none" stroke="#036f7b" stroke-width=".21"/>
<path d="M32.5 222.1h46.1v5.3h-46.1z" fill="#e6f1f2"/>
<path d="M32.5 222.1h46.1v5.3h-46.1z" fill="none" stroke="#036f7b" stroke-width=".21"/>
<path d="M78.7 222.1h69.2v5.3h-69.2z" fill="#e6f1f2"/>
<path d="M147.9 222.1h-69.3v5.3h69.3" fill="none" stroke="#036f7b" stroke-width=".21"/>
<path d="M147.9 222.1h3.8v5.3h-3.8z" fill="#e6f1f2"/>
<path d="M147.9 222.1h3.9v5.3h-3.9" fill="none" stroke="#036f7b" stroke-width=".21"/>
<path d="M151.9 222.1h15.7v5.3h-15.7z" fill="#e6f1f2"/>
<path d="M151.8 222.1h15.9v5.3h-15.9z" fill="none" stroke="#036f7b" stroke-width=".21"/>
<path d="M167.7 222.1h15.8v5.3h-15.8z" fill="#e6f1f2"/>
<path d="M167.7 222.1h15.8v5.3h-15.8z" fill="none" stroke="#036f7b" stroke-width=".21"/>
<path d="M183.6 222.1h8.7v5.3h-8.7z" fill="#e6f1f2"/>
<g fill="none" stroke="#036f7b" stroke-width=".21">
<path d="M17.6 222.1v42.9M17.7 222.1h174.7M32.5 222.1v42.9M78.6 222.1v42.9M151.8 222.1v42.9M167.7 222.1v42.9M183.5 222.1v42.9M192.4 222v43M192.4 227.4h-174.8M192.4 232.8h-174.8M192.4 238.2h-174.8M78.6 243.5h113.8"/>
<path d="M78.6 259.6h113.8M192.4 248.9h-174.8M192.4 254.2h-174.8M192.4 265h-174.8M17.6 282.6h174.8"/>
</g>
<use href="#words"/>
</svg>
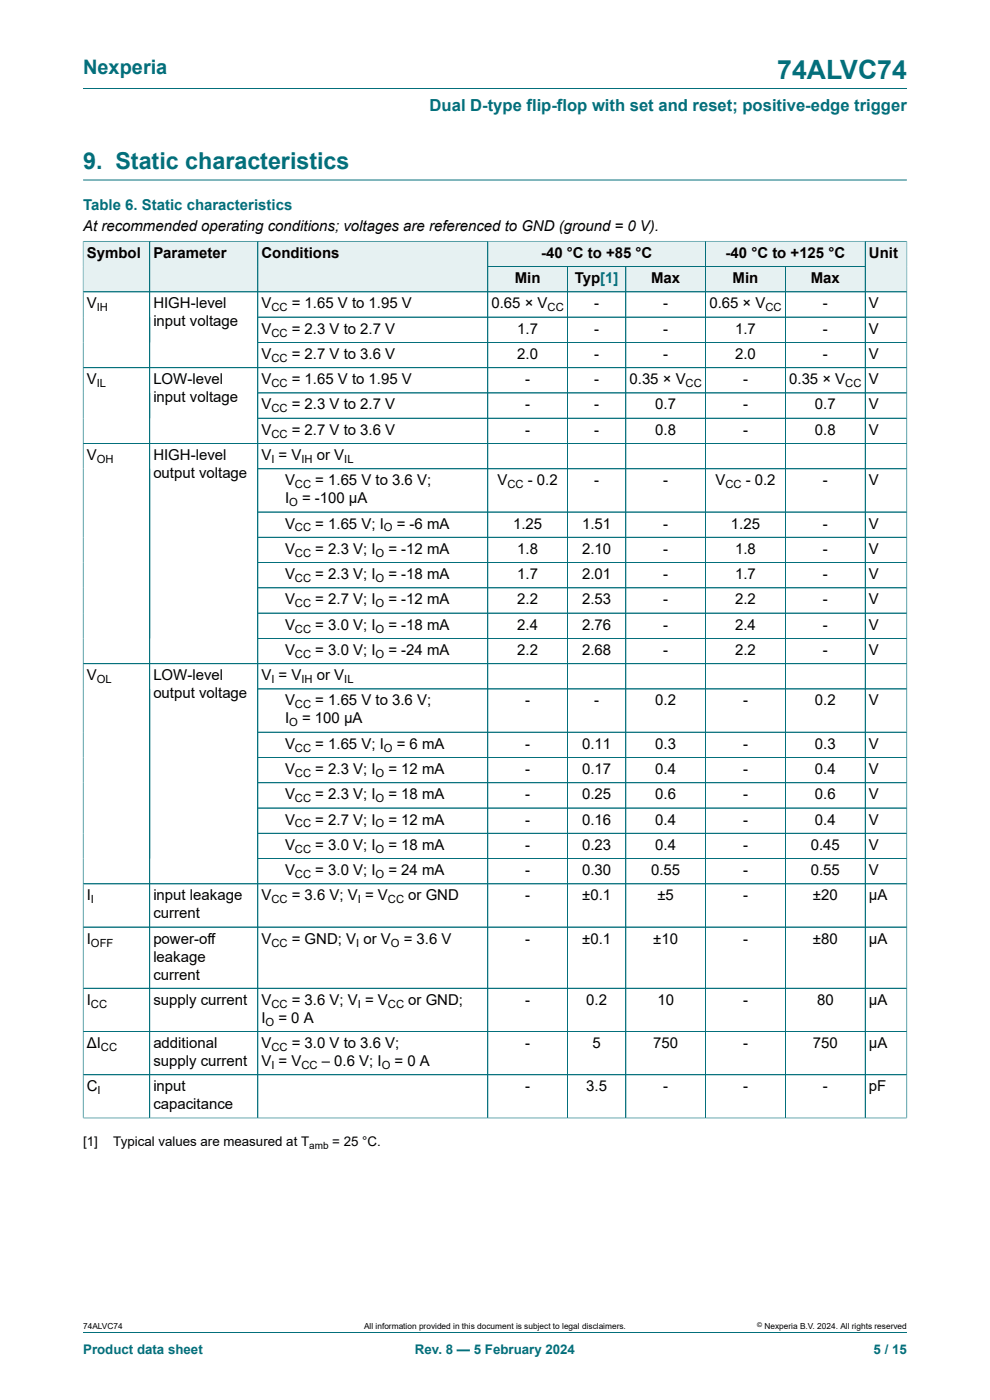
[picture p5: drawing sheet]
<svg xmlns="http://www.w3.org/2000/svg" width="210mm" height="297mm" viewBox="0 0 210 297" stroke-linecap="round" stroke-linejoin="round" font-family="sans-serif">
<defs><g id="words">
<text font-size="5.6" fill="#036f7b" x="164.9" y="16.8">74ALVC74</text>
<text font-size="4.9" fill="#036f7b" x="17.6" y="35.9">9. Static characteristics</text>
<text font-size="4.2" fill="#036f7b" x="17.6" y="15.6">Nexperia</text>
<text font-size="3.5" fill="#036f7b" x="91.1" y="23.7">Dual D-type flip-flop with set and reset; positive-edge trigger</text>
<text font-size="3.2" fill="#036f7b" x="17.6" y="44.5">Table 6. Static characteristics</text>
<g font-size="3.2">
<text x="17.6" y="49.1">At recommended operating conditions; voltages are referenced to GND (ground = 0 V).</text>
<text x="18.4" y="54.7">Symbol</text>
<text x="32.5" y="54.7">Parameter</text>
<text x="55.5" y="54.7">Conditions</text>
<text x="114.8" y="54.7">-40 °C to +85 °C</text>
<text x="153.9" y="54.7">-40 °C to +125 °C</text>
<text x="184.3" y="54.7">Unit</text>
<text x="18.4" y="65.4">V</text>
<text x="32.5" y="65.4">HIGH-level</text>
<text x="55.5" y="65.4">V</text>
<text x="61.9" y="65.4">= 1.65 V to 1.95 V</text>
<text x="104.3" y="65.4">0.65 × V</text>
<text x="109.2" y="60.1">Min</text>
<text x="121.9" y="60.1">Typ[1]</text>
<text x="126" y="65.4">-</text>
<text x="138.1" y="60.1">Max</text>
<text x="140.7" y="65.4">-</text>
<text x="150.5" y="65.4">0.65 × V</text>
<text x="155.4" y="60.1">Min</text>
<text x="172" y="60.1">Max</text>
<text x="174.5" y="65.4">-</text>
<text x="184.3" y="65.4">V</text>
<text x="32.5" y="69.2">input voltage</text>
<text x="55.5" y="70.8">V</text>
<text x="61.9" y="70.8">= 2.3 V to 2.7 V</text>
<text x="109.7" y="70.8">1.7</text>
<text x="126" y="70.8">-</text>
<text x="140.7" y="70.8">-</text>
<text x="155.9" y="70.8">1.7</text>
<text x="174.5" y="70.8">-</text>
<text x="184.3" y="70.8">V</text>
<text x="55.5" y="76.1">V</text>
<text x="61.9" y="76.1">= 2.7 V to 3.6 V</text>
<text x="109.7" y="76.1">2.0</text>
<text x="126" y="76.1">-</text>
<text x="140.7" y="76.1">-</text>
<text x="155.9" y="76.1">2.0</text>
<text x="174.5" y="76.1">-</text>
<text x="184.3" y="76.1">V</text>
<text x="18.4" y="81.5">V</text>
<text x="32.5" y="81.5">LOW-level</text>
<text x="55.5" y="81.5">V</text>
<text x="61.9" y="81.5">= 1.65 V to 1.95 V</text>
<text x="111.4" y="81.5">-</text>
<text x="126" y="81.5">-</text>
<text x="133.5" y="81.5">0.35 × V</text>
<text x="157.6" y="81.5">-</text>
<text x="167.4" y="81.5">0.35 × V</text>
<text x="184.3" y="81.5">V</text>
<text x="32.5" y="85.3">input voltage</text>
<text x="55.5" y="86.9">V</text>
<text x="61.9" y="86.9">= 2.3 V to 2.7 V</text>
<text x="111.4" y="86.9">-</text>
<text x="126" y="86.9">-</text>
<text x="139" y="86.9">0.7</text>
<text x="157.6" y="86.9">-</text>
<text x="172.9" y="86.9">0.7</text>
<text x="184.3" y="86.9">V</text>
<text x="55.5" y="92.2">V</text>
<text x="61.9" y="92.2">= 2.7 V to 3.6 V</text>
<text x="111.4" y="92.2">-</text>
<text x="126" y="92.2">-</text>
<text x="139" y="92.2">0.8</text>
<text x="157.6" y="92.2">-</text>
<text x="172.9" y="92.2">0.8</text>
<text x="184.3" y="92.2">V</text>
<text x="18.4" y="97.6">V</text>
<text x="32.5" y="97.6">HIGH-level</text>
<text x="32.5" y="101.4">output voltage</text>
<text x="55.5" y="97.6">V = V</text>
<text x="67.2" y="97.6">or V</text>
<text x="60.5" y="103">V</text>
<text x="60.5" y="106.8">I</text>
<text x="64.1" y="106.8">= -100 μA</text>
<text x="66.9" y="103">= 1.65 V to 3.6 V;</text>
<text x="105.5" y="103">V</text>
<text x="112" y="103">- 0.2</text>
<text x="126" y="103">-</text>
<text x="140.7" y="103">-</text>
<text x="151.8" y="103">V</text>
<text x="158.2" y="103">- 0.2</text>
<text x="174.5" y="103">-</text>
<text x="184.3" y="103">V</text>
<text x="60.5" y="112.1">V</text>
<text x="66.9" y="112.1">= 1.65 V; I</text>
<text x="84.2" y="112.1">= -6 mA</text>
<text x="108.8" y="112.1">1.25</text>
<text x="123.5" y="112.1">1.51</text>
<text x="140.7" y="112.1">-</text>
<text x="155.1" y="112.1">1.25</text>
<text x="174.5" y="112.1">-</text>
<text x="184.3" y="112.1">V</text>
<text x="60.5" y="117.5">V</text>
<text x="66.9" y="117.5">= 2.3 V; I</text>
<text x="82.4" y="117.5">= -12 mA</text>
<text x="109.7" y="117.5">1.8</text>
<text x="123.5" y="117.5">2.10</text>
<text x="140.7" y="117.5">-</text>
<text x="155.9" y="117.5">1.8</text>
<text x="174.5" y="117.5">-</text>
<text x="184.3" y="117.5">V</text>
<text x="60.5" y="122.8">V</text>
<text x="66.9" y="122.8">= 2.3 V; I</text>
<text x="82.4" y="122.8">= -18 mA</text>
<text x="109.7" y="122.8">1.7</text>
<text x="123.5" y="122.8">2.01</text>
<text x="140.7" y="122.8">-</text>
<text x="155.9" y="122.8">1.7</text>
<text x="174.5" y="122.8">-</text>
<text x="184.3" y="122.8">V</text>
<text x="60.5" y="128.2">V</text>
<text x="66.9" y="128.2">= 2.7 V; I</text>
<text x="82.4" y="128.2">= -12 mA</text>
<text x="109.7" y="128.2">2.2</text>
<text x="123.5" y="128.2">2.53</text>
<text x="140.7" y="128.2">-</text>
<text x="155.9" y="128.2">2.2</text>
<text x="174.5" y="128.2">-</text>
<text x="184.3" y="128.2">V</text>
<text x="60.5" y="133.6">V</text>
<text x="66.9" y="133.6">= 3.0 V; I</text>
<text x="82.4" y="133.6">= -18 mA</text>
<text x="109.7" y="133.6">2.4</text>
<text x="123.5" y="133.6">2.76</text>
<text x="140.7" y="133.6">-</text>
<text x="155.9" y="133.6">2.4</text>
<text x="174.5" y="133.6">-</text>
<text x="184.3" y="133.6">V</text>
<text x="60.5" y="138.9">V</text>
<text x="66.9" y="138.9">= 3.0 V; I</text>
<text x="82.4" y="138.9">= -24 mA</text>
<text x="109.7" y="138.9">2.2</text>
<text x="123.5" y="138.9">2.68</text>
<text x="140.7" y="138.9">-</text>
<text x="155.9" y="138.9">2.2</text>
<text x="174.5" y="138.9">-</text>
<text x="184.3" y="138.9">V</text>
<text x="18.4" y="144.3">V</text>
<text x="32.5" y="144.3">LOW-level</text>
<text x="32.5" y="148.1">output voltage</text>
<text x="55.5" y="144.3">V = V</text>
<text x="60.5" y="149.7">V</text>
<text x="66.9" y="149.7">= 1.65 V to 3.6 V;</text>
<text x="67.2" y="144.3">or V</text>
<text x="111.4" y="149.7">-</text>
<text x="126" y="149.7">-</text>
<text x="139" y="149.7">0.2</text>
<text x="157.6" y="149.7">-</text>
<text x="172.9" y="149.7">0.2</text>
<text x="184.3" y="149.7">V</text>
<text x="60.5" y="153.5">I</text>
<text x="64.1" y="153.5">= 100 μA</text>
<text x="60.5" y="158.8">V</text>
<text x="66.9" y="158.8">= 1.65 V; I</text>
<text x="84.2" y="158.8">= 6 mA</text>
<text x="111.4" y="158.8">-</text>
<text x="123.5" y="158.8">0.11</text>
<text x="139" y="158.8">0.3</text>
<text x="157.6" y="158.8">-</text>
<text x="172.9" y="158.8">0.3</text>
<text x="184.3" y="158.8">V</text>
<text x="60.5" y="164.2">V</text>
<text x="66.9" y="164.2">= 2.3 V; I</text>
<text x="82.4" y="164.2">= 12 mA</text>
<text x="111.4" y="164.2">-</text>
<text x="123.5" y="164.2">0.17</text>
<text x="139" y="164.2">0.4</text>
<text x="157.6" y="164.2">-</text>
<text x="172.9" y="164.2">0.4</text>
<text x="184.3" y="164.2">V</text>
<text x="60.5" y="169.6">V</text>
<text x="66.9" y="169.6">= 2.3 V; I</text>
<text x="82.4" y="169.6">= 18 mA</text>
<text x="111.4" y="169.6">-</text>
<text x="123.5" y="169.6">0.25</text>
<text x="139" y="169.6">0.6</text>
<text x="157.6" y="169.6">-</text>
<text x="172.9" y="169.6">0.6</text>
<text x="184.3" y="169.6">V</text>
<text x="60.5" y="174.9">V</text>
<text x="66.9" y="174.9">= 2.7 V; I</text>
<text x="82.4" y="174.9">= 12 mA</text>
<text x="111.4" y="174.9">-</text>
<text x="123.5" y="174.9">0.16</text>
<text x="139" y="174.9">0.4</text>
<text x="157.6" y="174.9">-</text>
<text x="172.9" y="174.9">0.4</text>
<text x="184.3" y="174.9">V</text>
<text x="60.5" y="180.3">V</text>
<text x="60.5" y="185.6">V</text>
<text x="66.9" y="180.3">= 3.0 V; I</text>
<text x="66.9" y="185.6">= 3.0 V; I</text>
<text x="82.4" y="180.3">= 18 mA</text>
<text x="82.4" y="185.6">= 24 mA</text>
<text x="111.4" y="180.3">-</text>
<text x="111.4" y="185.6">-</text>
<text x="123.5" y="180.3">0.23</text>
<text x="123.5" y="185.6">0.30</text>
<text x="138.1" y="185.6">0.55</text>
<text x="139" y="180.3">0.4</text>
<text x="157.6" y="180.3">-</text>
<text x="157.6" y="185.6">-</text>
<text x="172" y="180.3">0.45</text>
<text x="172" y="185.6">0.55</text>
<text x="184.3" y="180.3">V</text>
<text x="184.3" y="185.6">V</text>
<text x="18.4" y="191">I</text>
<text x="32.5" y="191">input leakage</text>
<text x="55.5" y="191">V</text>
<text x="61.9" y="191">= 3.6 V; V = V</text>
<text x="86.6" y="191">or GND</text>
<text x="111.4" y="191">-</text>
<text x="123.5" y="191">±0.1</text>
<text x="139.5" y="191">±5</text>
<text x="157.6" y="191">-</text>
<text x="172.4" y="191">±20</text>
<text x="184.3" y="191">μA</text>
<text x="32.5" y="194.8">current</text>
<text x="18.4" y="200.2">I</text>
<text x="32.5" y="200.2">power-off</text>
<text x="32.5" y="204">leakage</text>
<text x="55.5" y="200.2">V</text>
<text x="61.9" y="200.2">= GND; V or V</text>
<text x="85.6" y="200.2">= 3.6 V</text>
<text x="111.4" y="200.2">-</text>
<text x="123.5" y="200.2">±0.1</text>
<text x="138.6" y="200.2">±10</text>
<text x="157.6" y="200.2">-</text>
<text x="172.4" y="200.2">±80</text>
<text x="184.3" y="200.2">μA</text>
<text x="32.5" y="207.8">current</text>
<text x="18.4" y="213.2">I</text>
<text x="32.5" y="213.2">supply current</text>
<text x="55.5" y="213.2">V</text>
<text x="61.9" y="213.2">= 3.6 V; V = V</text>
<text x="86.6" y="213.2">or GND;</text>
<text x="111.4" y="213.2">-</text>
<text x="124.4" y="213.2">0.2</text>
<text x="139.4" y="213.2">10</text>
<text x="157.6" y="213.2">-</text>
<text x="173.3" y="213.2">80</text>
<text x="184.3" y="213.2">μA</text>
<text x="55.5" y="217">I</text>
<text x="59.1" y="217">= 0 A</text>
<text x="18.4" y="222.3">ΔI</text>
<text x="32.5" y="222.3">additional</text>
<text x="32.5" y="226.1">supply current</text>
<text x="55.5" y="222.3">V</text>
<text x="55.5" y="226.1">V = V</text>
<text x="61.9" y="222.3">= 3.0 V to 3.6 V;</text>
<text x="68.3" y="226.1">– 0.6 V; I</text>
<text x="83.7" y="226.1">= 0 A</text>
<text x="111.4" y="222.3">-</text>
<text x="125.7" y="222.3">5</text>
<text x="138.6" y="222.3">750</text>
<text x="157.6" y="222.3">-</text>
<text x="172.4" y="222.3">750</text>
<text x="184.3" y="222.3">μA</text>
<text x="18.4" y="231.5">C</text>
<text x="32.5" y="231.5">input</text>
<text x="111.4" y="231.5">-</text>
<text x="124.4" y="231.5">3.5</text>
<text x="140.7" y="231.5">-</text>
<text x="157.6" y="231.5">-</text>
<text x="174.5" y="231.5">-</text>
<text x="184.3" y="231.5">pF</text>
<text x="32.5" y="235.3">capacitance</text>
</g>
<g font-size="2.8">
<text x="17.6" y="243.1">[1]</text>
<text x="24" y="243.1">Typical values are measured at T</text>
<text x="70.5" y="243.1">= 25 °C.</text>
</g>
<g font-size="2.8" fill="#036f7b">
<text x="17.6" y="287.2">Product data sheet</text>
<text x="88" y="287.2">Rev. 8 — 5 February 2024</text>
<text x="185.3" y="287.2">5 / 15</text>
</g>
<g font-size="2.4">
<text x="20.5" y="66">IH</text>
<text x="57.6" y="66">CC</text>
<text x="57.6" y="71.4">CC</text>
<text x="116.2" y="66">CC</text>
<text x="162.4" y="66">CC</text>
<text x="57.6" y="76.8">CC</text>
<text x="20.5" y="82.1">IL</text>
<text x="57.6" y="82.1">CC</text>
<text x="145.4" y="82.1">CC</text>
<text x="179.3" y="82.1">CC</text>
<text x="57.6" y="87.5">CC</text>
<text x="57.6" y="92.8">CC</text>
<text x="20.5" y="98.2">OH</text>
<text x="57.6" y="98.2">I</text>
<text x="64" y="98.2">IH</text>
<text x="73" y="98.2">IL</text>
<text x="61.3" y="107.4">O</text>
<text x="62.6" y="103.6">CC</text>
<text x="107.7" y="103.6">CC</text>
<text x="153.9" y="103.6">CC</text>
<text x="62.6" y="112.7">CC</text>
<text x="81.4" y="112.7">O</text>
<text x="62.6" y="118.1">CC</text>
<text x="79.7" y="118.1">O</text>
<text x="62.6" y="123.5">CC</text>
<text x="79.7" y="123.5">O</text>
<text x="62.6" y="128.8">CC</text>
<text x="79.7" y="128.8">O</text>
<text x="62.6" y="134.2">CC</text>
<text x="79.7" y="134.2">O</text>
<text x="62.6" y="139.6">CC</text>
<text x="79.7" y="139.6">O</text>
<text x="20.5" y="144.9">OL</text>
<text x="57.6" y="144.9">I</text>
<text x="64" y="144.9">IH</text>
<text x="73" y="144.9">IL</text>
<text x="61.3" y="154.1">O</text>
<text x="62.6" y="150.3">CC</text>
<text x="62.6" y="159.4">CC</text>
<text x="81.4" y="159.4">O</text>
<text x="62.6" y="164.8">CC</text>
<text x="79.7" y="164.8">O</text>
<text x="62.6" y="170.2">CC</text>
<text x="79.7" y="170.2">O</text>
<text x="62.6" y="175.5">CC</text>
<text x="79.7" y="175.5">O</text>
<text x="62.6" y="180.9">CC</text>
<text x="79.7" y="180.9">O</text>
<text x="19.3" y="191.6">I</text>
<text x="57.6" y="191.6">CC</text>
<text x="62.6" y="186.3">CC</text>
<text x="75.9" y="191.6">I</text>
<text x="79.7" y="186.3">O</text>
<text x="82.3" y="191.6">CC</text>
<text x="19.3" y="200.8">OFF</text>
<text x="57.6" y="200.8">CC</text>
<text x="75.5" y="200.8">I</text>
<text x="82.9" y="200.8">O</text>
<text x="19.3" y="213.8">CC</text>
<text x="57.6" y="213.8">CC</text>
<text x="75.9" y="213.8">I</text>
<text x="82.3" y="213.8">CC</text>
<text x="56.3" y="217.6">O</text>
<text x="21.4" y="222.9">CC</text>
<text x="57.6" y="222.9">CC</text>
<text x="57.6" y="226.8">I</text>
<text x="64" y="226.8">CC</text>
<text x="81" y="226.8">O</text>
<text x="20.7" y="232.1">I</text>
</g>
<text font-size="2.1" x="65.6" y="243.7">amb</text>
<g font-size="1.8">
<text x="17.6" y="282">74ALVC74</text>
<text x="77.2" y="282">All information provided in this document is subject to legal disclaimers.</text>
<text x="162.2" y="282">Nexperia B.V. 2024. All rights reserved</text>
</g>
<text font-size="1.4" x="160.6" y="281.6">©</text>
</g></defs>
<path d="M17.6 18.8h174.8M17.6 38.2h174.8M103.5 51.2h46.2v5.4h-46.2z" fill="none" stroke="#036f7b" stroke-width=".21"/>
<path d="M103.5 51.3h46.1v5.2h-46.1z" fill="#e6f1f2"/>
<path d="M149.7 51.2h33.8v5.4h-33.8z" fill="none" stroke="#036f7b" stroke-width=".21"/>
<path d="M149.7 51.3h33.8v5.2h-33.8z" fill="#e6f1f2"/>
<path d="M17.6 51.1v10.8h14.1v-10.7h-14.1" fill="none" stroke="#036f7b" stroke-width=".21"/>
<path d="M17.7 51.3h14v10.5h-14z" fill="#e6f1f2"/>
<path d="M31.7 51.2h23v10.7h-23z" fill="none" stroke="#036f7b" stroke-width=".21"/>
<path d="M31.8 51.3h22.8v10.5h-22.8z" fill="#e6f1f2"/>
<path d="M54.7 51.2h48.8v10.7h-48.8z" fill="none" stroke="#036f7b" stroke-width=".21"/>
<g fill="#e6f1f2">
<path d="M54.8 51.3h48.6v10.5h-48.6z"/>
<path d="M103.5 56.6h16.8v5.2h-16.8z"/>
</g>
<path d="M103.5 56.6h16.9v5.3h-16.9z" fill="none" stroke="#036f7b" stroke-width=".21"/>
<path d="M120.5 56.6h12.2v5.2h-12.2z" fill="#e6f1f2"/>
<path d="M120.4 56.6h12.3v5.3h-12.3z" fill="none" stroke="#036f7b" stroke-width=".21"/>
<path d="M132.8 56.6h16.8v5.2h-16.8z" fill="#e6f1f2"/>
<path d="M132.7 56.6h17v5.3h-17z" fill="none" stroke="#036f7b" stroke-width=".21"/>
<path d="M149.7 56.6h16.8v5.2h-16.8z" fill="#e6f1f2"/>
<path d="M149.7 56.6h16.9v5.3h-16.9z" fill="none" stroke="#036f7b" stroke-width=".21"/>
<path d="M166.7 56.6h16.8v5.2h-16.8z" fill="#e6f1f2"/>
<path d="M192.4 51.1v10.8h-25.8v-5.3h16.9M192.4 51.2h-8.9v10.7" fill="none" stroke="#036f7b" stroke-width=".21"/>
<path d="M183.6 51.3h8.7v10.5h-8.7z" fill="#e6f1f2"/>
<g fill="none" stroke="#036f7b" stroke-width=".21">
<path d="M17.6 51.3v185.9M17.7 51.2h174.6M31.7 51.3v185.9M54.7 51.3v185.9M103.5 51.3v185.9M103.5 56.6h80M120.4 56.6v180.6M132.7 56.6v180.6M149.7 51.3v185.9M166.6 56.6v180.6M183.5 51.3v185.9M192.4 51.3v185.9"/>
<path d="M17.6 61.9h174.8M17.6 78h174.8M54.7 67.3h137.7M54.7 72.6h137.7M17.6 94.1h174.8M54.7 88.7h137.7M54.7 99.4h137.7M192.4 83.4h-137.7M54.7 108.6h137.7M54.7 114h137.7M192.4 119.3h-137.7M54.7 124.7h137.7"/>
<path d="M192.4 130.1h-137.7M192.4 135.4h-137.7M17.6 140.8h174.8M54.7 155.3h137.7M192.4 146.2h-137.7M54.7 160.7h137.7M54.7 176.8h137.7M192.4 166.1h-137.7M192.4 171.4h-137.7M17.6 187.5h174.8M17.6 196.7h174.8M192.4 182.1h-137.7"/>
<path d="M17.6 209.7h174.8M17.6 218.8h174.8M17.6 237.2h174.8M17.6 228h174.8M17.6 282.6h174.8"/>
</g>
<use href="#words"/>
</svg>
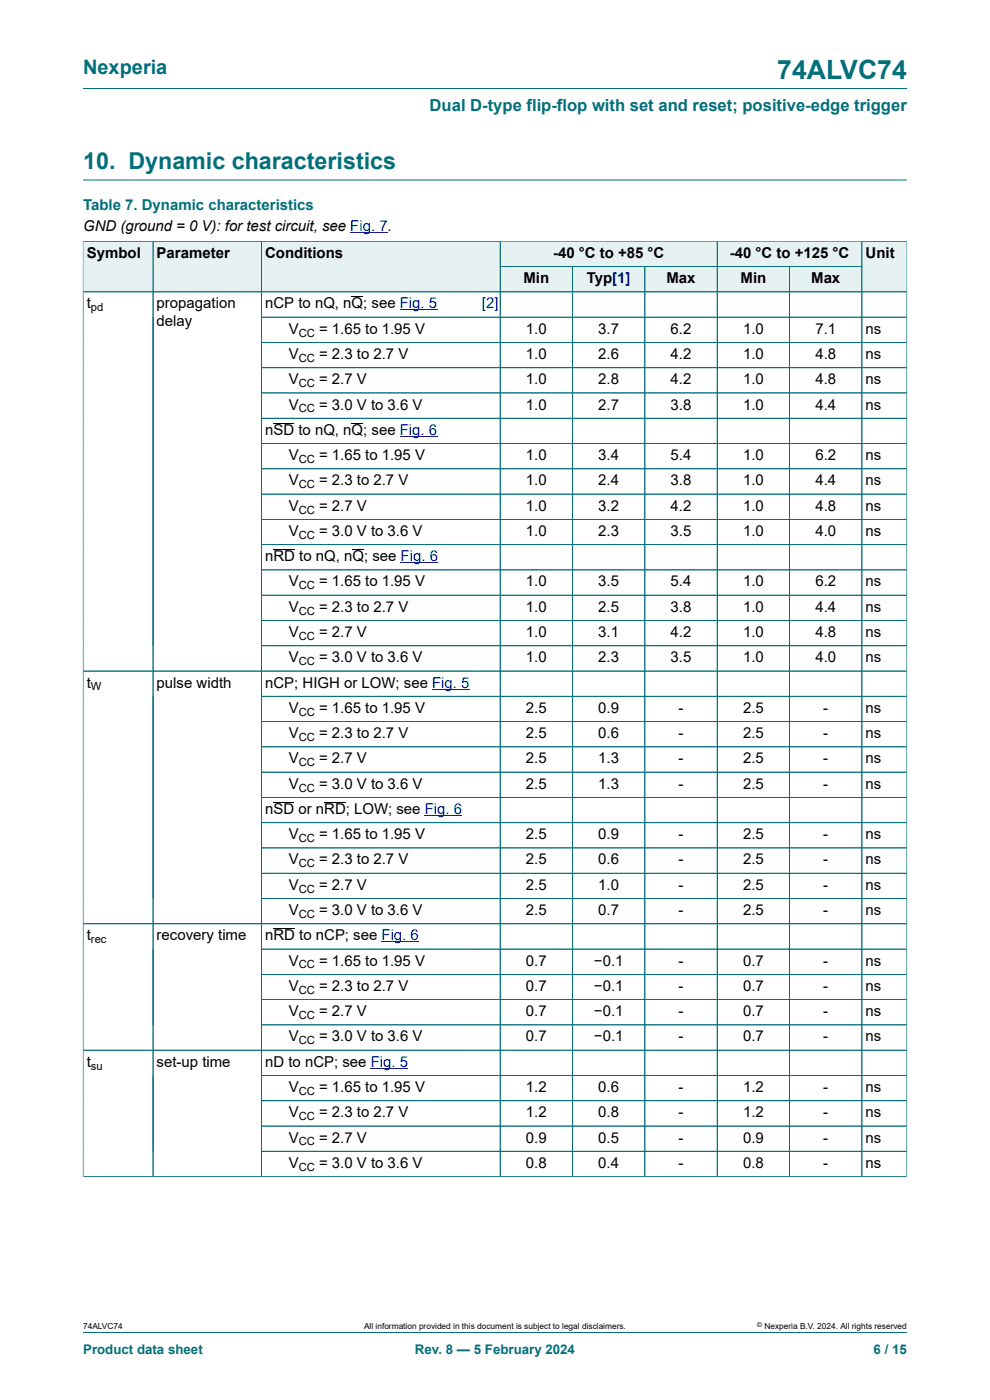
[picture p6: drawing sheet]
<svg xmlns="http://www.w3.org/2000/svg" width="210mm" height="297mm" viewBox="0 0 210 297" stroke-linecap="round" stroke-linejoin="round" font-family="sans-serif">
<defs><g id="words">
<text font-size="5.6" fill="#036f7b" x="164.9" y="16.8">74ALVC74</text>
<text font-size="4.9" fill="#036f7b" x="17.6" y="35.9">10. Dynamic characteristics</text>
<text font-size="4.2" fill="#036f7b" x="17.6" y="15.6">Nexperia</text>
<text font-size="3.5" fill="#036f7b" x="91.1" y="23.7">Dual D-type flip-flop with set and reset; positive-edge trigger</text>
<text font-size="3.2" fill="#036f7b" x="17.6" y="44.5">Table 7. Dynamic characteristics</text>
<g font-size="3.2">
<text x="17.6" y="49.1">GND (ground = 0 V): for test circuit, see Fig. 7.</text>
<text x="18.4" y="54.7">Symbol</text>
<text x="33.2" y="54.7">Parameter</text>
<text x="56.3" y="54.7">Conditions</text>
<text x="117.3" y="54.7">-40 °C to +85 °C</text>
<text x="154.8" y="54.7">-40 °C to +125 °C</text>
<text x="183.6" y="54.7">Unit</text>
<text x="18.4" y="65.4">t</text>
<text x="33.2" y="65.4">propagation</text>
<text x="56.3" y="65.4">nCP to nQ, nQ; see Fig. 5</text>
<text x="111" y="60.1">Min</text>
<text x="124.5" y="60.1">Typ[1]</text>
<text x="141.4" y="60.1">Max</text>
<text x="157.1" y="60.1">Min</text>
<text x="172.1" y="60.1">Max</text>
<text x="33.2" y="69.2">delay</text>
<text x="61.3" y="70.8">V</text>
<text x="67.7" y="70.8">= 1.65 to 1.95 V</text>
<text x="111.6" y="70.8">1.0</text>
<text x="126.9" y="70.8">3.7</text>
<text x="142.3" y="70.8">6.2</text>
<text x="157.6" y="70.8">1.0</text>
<text x="173" y="70.8">7.1</text>
<text x="183.6" y="70.8">ns</text>
<text x="61.3" y="76.1">V</text>
<text x="67.7" y="76.1">= 2.3 to 2.7 V</text>
<text x="111.6" y="76.1">1.0</text>
<text x="126.9" y="76.1">2.6</text>
<text x="142.3" y="76.1">4.2</text>
<text x="157.6" y="76.1">1.0</text>
<text x="173" y="76.1">4.8</text>
<text x="183.6" y="76.1">ns</text>
<text x="61.3" y="81.5">V</text>
<text x="67.7" y="81.5">= 2.7 V</text>
<text x="111.6" y="81.5">1.0</text>
<text x="126.9" y="81.5">2.8</text>
<text x="142.3" y="81.5">4.2</text>
<text x="157.6" y="81.5">1.0</text>
<text x="173" y="81.5">4.8</text>
<text x="183.6" y="81.5">ns</text>
<text x="61.3" y="86.9">V</text>
<text x="67.7" y="86.9">= 3.0 V to 3.6 V</text>
<text x="111.6" y="86.9">1.0</text>
<text x="126.9" y="86.9">2.7</text>
<text x="142.3" y="86.9">3.8</text>
<text x="157.6" y="86.9">1.0</text>
<text x="173" y="86.9">4.4</text>
<text x="183.6" y="86.9">ns</text>
<text x="56.3" y="92.2">nSD to nQ, nQ; see Fig. 6</text>
<text x="61.3" y="97.6">V</text>
<text x="67.7" y="97.6">= 1.65 to 1.95 V</text>
<text x="111.6" y="97.6">1.0</text>
<text x="126.9" y="97.6">3.4</text>
<text x="142.3" y="97.6">5.4</text>
<text x="157.6" y="97.6">1.0</text>
<text x="173" y="97.6">6.2</text>
<text x="183.6" y="97.6">ns</text>
<text x="61.3" y="103">V</text>
<text x="67.7" y="103">= 2.3 to 2.7 V</text>
<text x="111.6" y="103">1.0</text>
<text x="126.9" y="103">2.4</text>
<text x="142.3" y="103">3.8</text>
<text x="157.6" y="103">1.0</text>
<text x="173" y="103">4.4</text>
<text x="183.6" y="103">ns</text>
<text x="61.3" y="108.3">V</text>
<text x="61.3" y="113.7">V</text>
<text x="67.7" y="108.3">= 2.7 V</text>
<text x="67.7" y="113.7">= 3.0 V to 3.6 V</text>
<text x="111.6" y="108.3">1.0</text>
<text x="111.6" y="113.7">1.0</text>
<text x="126.9" y="108.3">3.2</text>
<text x="126.9" y="113.7">2.3</text>
<text x="142.3" y="108.3">4.2</text>
<text x="142.3" y="113.7">3.5</text>
<text x="157.6" y="108.3">1.0</text>
<text x="157.6" y="113.7">1.0</text>
<text x="173" y="108.3">4.8</text>
<text x="173" y="113.7">4.0</text>
<text x="183.6" y="108.3">ns</text>
<text x="183.6" y="113.7">ns</text>
<text x="56.3" y="119">nRD to nQ, nQ; see Fig. 6</text>
<text x="61.3" y="124.4">V</text>
<text x="67.7" y="124.4">= 1.65 to 1.95 V</text>
<text x="111.6" y="124.4">1.0</text>
<text x="126.9" y="124.4">3.5</text>
<text x="142.3" y="124.4">5.4</text>
<text x="157.6" y="124.4">1.0</text>
<text x="173" y="124.4">6.2</text>
<text x="183.6" y="124.4">ns</text>
<text x="61.3" y="129.8">V</text>
<text x="67.7" y="129.8">= 2.3 to 2.7 V</text>
<text x="111.6" y="129.8">1.0</text>
<text x="126.9" y="129.8">2.5</text>
<text x="142.3" y="129.8">3.8</text>
<text x="157.6" y="129.8">1.0</text>
<text x="173" y="129.8">4.4</text>
<text x="183.6" y="129.8">ns</text>
<text x="61.3" y="135.1">V</text>
<text x="67.7" y="135.1">= 2.7 V</text>
<text x="111.6" y="135.1">1.0</text>
<text x="126.9" y="135.1">3.1</text>
<text x="142.3" y="135.1">4.2</text>
<text x="157.6" y="135.1">1.0</text>
<text x="173" y="135.1">4.8</text>
<text x="183.6" y="135.1">ns</text>
<text x="61.3" y="140.5">V</text>
<text x="67.7" y="140.5">= 3.0 V to 3.6 V</text>
<text x="111.6" y="140.5">1.0</text>
<text x="126.9" y="140.5">2.3</text>
<text x="142.3" y="140.5">3.5</text>
<text x="157.6" y="140.5">1.0</text>
<text x="173" y="140.5">4.0</text>
<text x="183.6" y="140.5">ns</text>
<text x="18.4" y="145.9">t</text>
<text x="33.2" y="145.9">pulse width</text>
<text x="56.3" y="145.9">nCP; HIGH or LOW; see Fig. 5</text>
<text x="61.3" y="151.2">V</text>
<text x="67.7" y="151.2">= 1.65 to 1.95 V</text>
<text x="111.6" y="151.2">2.5</text>
<text x="126.9" y="151.2">0.9</text>
<text x="143.9" y="151.2">-</text>
<text x="157.6" y="151.2">2.5</text>
<text x="174.6" y="151.2">-</text>
<text x="183.6" y="151.2">ns</text>
<text x="61.3" y="156.6">V</text>
<text x="61.3" y="161.9">V</text>
<text x="67.7" y="156.6">= 2.3 to 2.7 V</text>
<text x="67.7" y="161.9">= 2.7 V</text>
<text x="111.6" y="156.6">2.5</text>
<text x="111.6" y="161.9">2.5</text>
<text x="126.9" y="156.6">0.6</text>
<text x="126.9" y="161.9">1.3</text>
<text x="143.9" y="156.6">-</text>
<text x="143.9" y="161.9">-</text>
<text x="157.6" y="156.6">2.5</text>
<text x="157.6" y="161.9">2.5</text>
<text x="174.6" y="156.6">-</text>
<text x="174.6" y="161.9">-</text>
<text x="183.6" y="156.6">ns</text>
<text x="183.6" y="161.9">ns</text>
<text x="61.3" y="167.3">V</text>
<text x="67.7" y="167.3">= 3.0 V to 3.6 V</text>
<text x="111.6" y="167.3">2.5</text>
<text x="126.9" y="167.3">1.3</text>
<text x="143.9" y="167.3">-</text>
<text x="157.6" y="167.3">2.5</text>
<text x="174.6" y="167.3">-</text>
<text x="183.6" y="167.3">ns</text>
<text x="56.3" y="172.7">nSD or nRD; LOW; see Fig. 6</text>
<text x="61.3" y="178">V</text>
<text x="67.7" y="178">= 1.65 to 1.95 V</text>
<text x="111.6" y="178">2.5</text>
<text x="126.9" y="178">0.9</text>
<text x="143.9" y="178">-</text>
<text x="157.6" y="178">2.5</text>
<text x="174.6" y="178">-</text>
<text x="183.6" y="178">ns</text>
<text x="61.3" y="183.4">V</text>
<text x="67.7" y="183.4">= 2.3 to 2.7 V</text>
<text x="111.6" y="183.4">2.5</text>
<text x="126.9" y="183.4">0.6</text>
<text x="143.9" y="183.4">-</text>
<text x="157.6" y="183.4">2.5</text>
<text x="174.6" y="183.4">-</text>
<text x="183.6" y="183.4">ns</text>
<text x="61.3" y="188.8">V</text>
<text x="67.7" y="188.8">= 2.7 V</text>
<text x="111.6" y="188.8">2.5</text>
<text x="126.9" y="188.8">1.0</text>
<text x="143.9" y="188.8">-</text>
<text x="157.6" y="188.8">2.5</text>
<text x="174.6" y="188.8">-</text>
<text x="183.6" y="188.8">ns</text>
<text x="61.3" y="194.1">V</text>
<text x="67.7" y="194.1">= 3.0 V to 3.6 V</text>
<text x="111.6" y="194.1">2.5</text>
<text x="126.9" y="194.1">0.7</text>
<text x="143.9" y="194.1">-</text>
<text x="157.6" y="194.1">2.5</text>
<text x="174.6" y="194.1">-</text>
<text x="183.6" y="194.1">ns</text>
<text x="18.4" y="199.5">t</text>
<text x="33.2" y="199.5">recovery time</text>
<text x="56.3" y="199.5">nRD to nCP; see Fig. 6</text>
<text x="61.3" y="204.8">V</text>
<text x="67.7" y="204.8">= 1.65 to 1.95 V</text>
<text x="111.6" y="204.8">0.7</text>
<text x="126" y="204.8">−0.1</text>
<text x="143.9" y="204.8">-</text>
<text x="157.6" y="204.8">0.7</text>
<text x="174.6" y="204.8">-</text>
<text x="183.6" y="204.8">ns</text>
<text x="61.3" y="210.2">V</text>
<text x="61.3" y="215.6">V</text>
<text x="67.7" y="210.2">= 2.3 to 2.7 V</text>
<text x="67.7" y="215.6">= 2.7 V</text>
<text x="111.6" y="210.2">0.7</text>
<text x="111.6" y="215.6">0.7</text>
<text x="126" y="210.2">−0.1</text>
<text x="126" y="215.6">−0.1</text>
<text x="143.9" y="210.2">-</text>
<text x="143.9" y="215.6">-</text>
<text x="157.6" y="210.2">0.7</text>
<text x="157.6" y="215.6">0.7</text>
<text x="174.6" y="210.2">-</text>
<text x="174.6" y="215.6">-</text>
<text x="183.6" y="210.2">ns</text>
<text x="183.6" y="215.6">ns</text>
<text x="61.3" y="220.9">V</text>
<text x="67.7" y="220.9">= 3.0 V to 3.6 V</text>
<text x="111.6" y="220.9">0.7</text>
<text x="126" y="220.9">−0.1</text>
<text x="143.9" y="220.9">-</text>
<text x="157.6" y="220.9">0.7</text>
<text x="174.6" y="220.9">-</text>
<text x="183.6" y="220.9">ns</text>
<text x="18.4" y="226.3">t</text>
<text x="33.2" y="226.3">set-up time</text>
<text x="56.3" y="226.3">nD to nCP; see Fig. 5</text>
<text x="61.3" y="231.7">V</text>
<text x="67.7" y="231.7">= 1.65 to 1.95 V</text>
<text x="111.6" y="231.7">1.2</text>
<text x="126.9" y="231.7">0.6</text>
<text x="143.9" y="231.7">-</text>
<text x="157.6" y="231.7">1.2</text>
<text x="174.6" y="231.7">-</text>
<text x="183.6" y="231.7">ns</text>
<text x="61.3" y="237">V</text>
<text x="67.7" y="237">= 2.3 to 2.7 V</text>
<text x="111.6" y="237">1.2</text>
<text x="126.9" y="237">0.8</text>
<text x="143.9" y="237">-</text>
<text x="157.6" y="237">1.2</text>
<text x="174.6" y="237">-</text>
<text x="183.6" y="237">ns</text>
<text x="61.3" y="242.4">V</text>
<text x="67.7" y="242.4">= 2.7 V</text>
<text x="111.6" y="242.4">0.9</text>
<text x="126.9" y="242.4">0.5</text>
<text x="143.9" y="242.4">-</text>
<text x="157.6" y="242.4">0.9</text>
<text x="174.6" y="242.4">-</text>
<text x="183.6" y="242.4">ns</text>
<text x="61.3" y="247.7">V</text>
<text x="67.7" y="247.7">= 3.0 V to 3.6 V</text>
<text x="111.6" y="247.7">0.8</text>
<text x="126.9" y="247.7">0.4</text>
<text x="143.9" y="247.7">-</text>
<text x="157.6" y="247.7">0.8</text>
<text x="174.6" y="247.7">-</text>
<text x="183.6" y="247.7">ns</text>
</g>
<text font-size="3.2" fill="#00f" x="102.2" y="65.4">[2]</text>
<g font-size="2.8" fill="#036f7b">
<text x="17.6" y="287.2">Product data sheet</text>
<text x="88" y="287.2">Rev. 8 — 5 February 2024</text>
<text x="185.3" y="287.2">6 / 15</text>
</g>
<g font-size="2.4">
<text x="19.3" y="66">pd</text>
<text x="63.4" y="71.4">CC</text>
<text x="63.4" y="76.8">CC</text>
<text x="63.4" y="82.1">CC</text>
<text x="63.4" y="87.5">CC</text>
<text x="63.4" y="98.2">CC</text>
<text x="63.4" y="103.6">CC</text>
<text x="63.4" y="108.9">CC</text>
<text x="63.4" y="114.3">CC</text>
<text x="63.4" y="125">CC</text>
<text x="63.4" y="130.4">CC</text>
<text x="63.4" y="135.8">CC</text>
<text x="63.4" y="141.1">CC</text>
<text x="19.3" y="146.5">W</text>
<text x="63.4" y="151.8">CC</text>
<text x="63.4" y="157.2">CC</text>
<text x="63.4" y="162.6">CC</text>
<text x="63.4" y="167.9">CC</text>
<text x="63.4" y="178.6">CC</text>
<text x="63.4" y="184">CC</text>
<text x="63.4" y="189.4">CC</text>
<text x="63.4" y="194.7">CC</text>
<text x="19.3" y="200.1">rec</text>
<text x="63.4" y="205.5">CC</text>
<text x="63.4" y="210.8">CC</text>
<text x="63.4" y="216.2">CC</text>
<text x="63.4" y="221.5">CC</text>
<text x="19.3" y="226.9">su</text>
<text x="63.4" y="232.3">CC</text>
<text x="63.4" y="237.6">CC</text>
<text x="63.4" y="243">CC</text>
<text x="63.4" y="248.4">CC</text>
</g>
<g font-size="1.8">
<text x="17.6" y="282">74ALVC74</text>
<text x="77.2" y="282">All information provided in this document is subject to legal disclaimers.</text>
<text x="162.2" y="282">Nexperia B.V. 2024. All rights reserved</text>
</g>
<text font-size="1.4" x="160.6" y="281.6">©</text>
</g></defs>
<path d="M17.6 18.8h174.8M17.6 38.2h174.8M106.1 51.2h46v5.4h-46z" fill="none" stroke="#036f7b" stroke-width=".21"/>
<path d="M74.3 49.4h7.9" fill="none" stroke="#00f" stroke-width=".21"/>
<path d="M106.2 51.3h45.9v5.2h-45.9z" fill="#e6f1f2"/>
<path d="M152.1 51.2h30.7v5.4h-30.7z" fill="none" stroke="#036f7b" stroke-width=".21"/>
<path d="M152.2 51.3h30.6v5.2h-30.6z" fill="#e6f1f2"/>
<path d="M17.6 51.1v10.8h14.9v-10.7h-14.9" fill="none" stroke="#036f7b" stroke-width=".21"/>
<path d="M17.7 51.3h14.7v10.6h-14.7z" fill="#e6f1f2"/>
<path d="M32.5 51.2h23v10.7h-23z" fill="none" stroke="#036f7b" stroke-width=".21"/>
<path d="M32.5 51.3h22.9v10.6h-22.9z" fill="#e6f1f2"/>
<path d="M101.5 51.2h-46v10.7h46" fill="none" stroke="#036f7b" stroke-width=".21"/>
<path d="M55.5 51.3h46v10.6h-46z" fill="#e6f1f2"/>
<path d="M101.5 51.2h4.6v10.7h-4.6" fill="none" stroke="#036f7b" stroke-width=".21"/>
<g fill="#e6f1f2">
<path d="M101.5 51.3h4.5v10.6h-4.5z"/>
<path d="M106.2 56.6h15.2v5.3h-15.2z"/>
</g>
<path d="M106.1 56.6h15.3v5.3h-15.3z" fill="none" stroke="#036f7b" stroke-width=".21"/>
<path d="M121.5 56.6h15.2v5.3h-15.2z" fill="#e6f1f2"/>
<path d="M121.4 56.6h15.4v5.3h-15.4z" fill="none" stroke="#036f7b" stroke-width=".21"/>
<path d="M136.9 56.6h15.2v5.3h-15.2z" fill="#e6f1f2"/>
<path d="M136.8 56.6h15.3v5.3h-15.3z" fill="none" stroke="#036f7b" stroke-width=".21"/>
<path d="M152.2 56.6h15.2v5.3h-15.2z" fill="#e6f1f2"/>
<path d="M152.1 56.6h15.4v5.3h-15.4z" fill="none" stroke="#036f7b" stroke-width=".21"/>
<path d="M167.6 56.6h15.2v5.3h-15.2z" fill="#e6f1f2"/>
<path d="M192.4 51.1v10.8h-24.9v-5.3h15.3M192.4 51.2h-9.6v10.7" fill="none" stroke="#036f7b" stroke-width=".21"/>
<path d="M182.9 51.3h9.4v10.6h-9.4z" fill="#e6f1f2"/>
<g fill="none" stroke="#036f7b" stroke-width=".21">
<path d="M17.6 51.3v198.4M17.7 51.2h174.6M32.5 51.3v198.3M55.5 51.3v198.3M106.1 51.3v198.3M106.2 56.6h76.6M121.4 56.6v193M136.8 56.6v193M152.1 51.3v198.3M167.5 56.6v193M182.8 51.3v198.3M192.4 51.3v198.4"/>
<path d="M17.6 61.9h174.8M55.5 67.3h136.9M55.5 72.6h136.9M55.5 78h136.9M55.5 83.4h136.9M55.5 88.7h136.9M55.5 94.1h136.9M55.5 99.5h136.9M55.5 104.8h136.9M55.5 110.2h136.9M55.5 115.5h136.9M55.5 120.9h136.9"/>
<path d="M55.5 126.3h136.9M55.5 131.6h136.9M55.5 137h136.9M17.6 142.4h174.8M55.5 147.7h136.9M55.5 153.1h136.9M55.5 158.4h136.9M55.5 163.8h136.9M55.5 169.2h136.9M55.5 174.5h136.9M55.5 179.9h136.9M17.6 196h174.8"/>
<path d="M55.5 185.3h136.9M55.5 190.6h136.9M55.5 201.3h136.9M55.5 206.7h136.9M55.5 212.1h136.9M55.5 217.4h136.9M55.5 228.2h136.9M55.5 233.5h136.9M55.5 238.9h136.9M192.4 222.8h-174.8M55.5 244.2h136.9M192.4 249.6h-174.8"/>
<path d="M17.6 282.6h174.8"/>
</g>
<path d="M74.6 62.9h2.5M58 89.7h4.4M74.6 89.7h2.5M58 116.6h4.6M74.8 116.6h2.4M58 170.2h4.4M68.8 170.2h4.6M58 197h4.6" fill="none" stroke="#000" stroke-width=".21"/>
<path d="M84.8 65.8h7.9M84.8 92.6h7.9M85 119.4h7.9M91.7 146.2h7.9M90.1 173h7.9M80.9 199.8h8M78.6 226.6h8" fill="none" stroke="#00f" stroke-width=".21"/>
<use href="#words"/>
</svg>
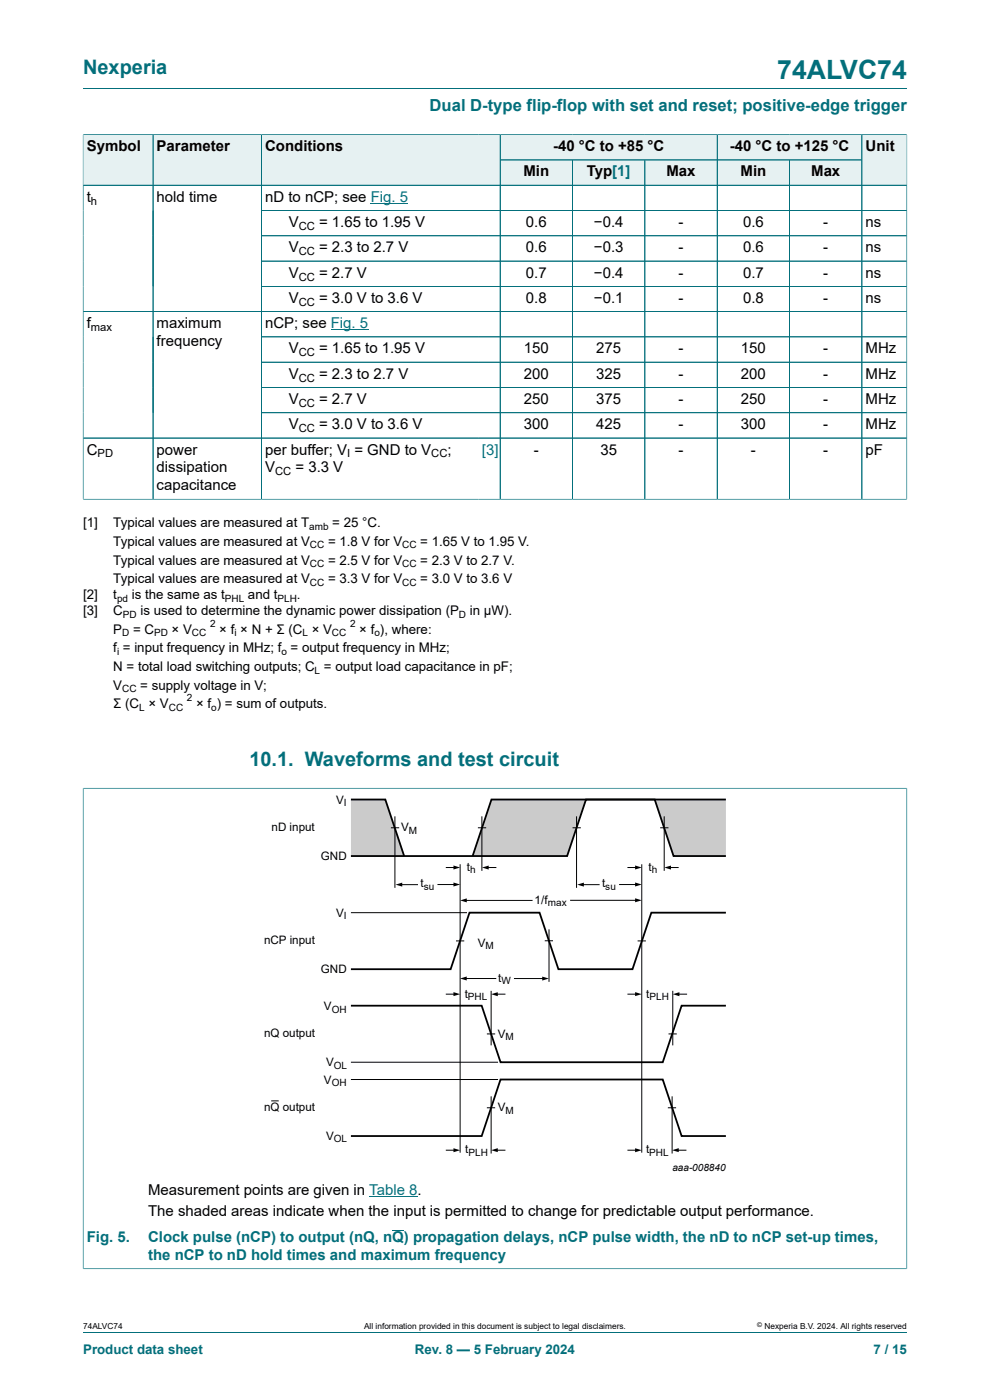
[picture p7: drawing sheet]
<svg xmlns="http://www.w3.org/2000/svg" width="210mm" height="297mm" viewBox="0 0 210 297" stroke-linecap="round" stroke-linejoin="round" font-family="sans-serif">
<defs><g id="words">
<text font-size="5.6" fill="#036f7b" x="164.9" y="16.8">74ALVC74</text>
<g font-size="4.2" fill="#036f7b">
<text x="17.6" y="15.6">Nexperia</text>
<text x="52.9" y="162.6">10.1. Waveforms and test circuit</text>
</g>
<text font-size="3.5" fill="#036f7b" x="91.1" y="23.7">Dual D-type flip-flop with set and reset; positive-edge trigger</text>
<g font-size="3.2">
<text x="18.4" y="32.1">Symbol</text>
<text x="33.2" y="32.1">Parameter</text>
<text x="56.3" y="32.1">Conditions</text>
<text x="117.3" y="32.1">-40 °C to +85 °C</text>
<text x="154.8" y="32.1">-40 °C to +125 °C</text>
<text x="183.6" y="32.1">Unit</text>
<text x="111" y="37.4">Min</text>
<text x="124.5" y="37.4">Typ[1]</text>
<text x="141.4" y="37.4">Max</text>
<text x="157.1" y="37.4">Min</text>
<text x="172.1" y="37.4">Max</text>
<text x="18.4" y="42.8">t</text>
<text x="33.2" y="42.8">hold time</text>
<text x="56.3" y="42.8">nD to nCP; see Fig. 5</text>
<text x="61.3" y="48.2">V</text>
<text x="61.3" y="53.5">V</text>
<text x="67.7" y="48.2">= 1.65 to 1.95 V</text>
<text x="67.7" y="53.5">= 2.3 to 2.7 V</text>
<text x="111.6" y="48.2">0.6</text>
<text x="111.6" y="53.5">0.6</text>
<text x="126" y="48.2">−0.4</text>
<text x="126" y="53.5">−0.3</text>
<text x="143.9" y="48.2">-</text>
<text x="143.9" y="53.5">-</text>
<text x="157.6" y="48.2">0.6</text>
<text x="157.6" y="53.5">0.6</text>
<text x="174.6" y="48.2">-</text>
<text x="174.6" y="53.5">-</text>
<text x="183.6" y="48.2">ns</text>
<text x="183.6" y="53.5">ns</text>
<text x="61.3" y="58.9">V</text>
<text x="67.7" y="58.9">= 2.7 V</text>
<text x="111.6" y="58.9">0.7</text>
<text x="126" y="58.9">−0.4</text>
<text x="143.9" y="58.9">-</text>
<text x="157.6" y="58.9">0.7</text>
<text x="174.6" y="58.9">-</text>
<text x="183.6" y="58.9">ns</text>
<text x="61.3" y="64.3">V</text>
<text x="67.7" y="64.3">= 3.0 V to 3.6 V</text>
<text x="111.6" y="64.3">0.8</text>
<text x="126" y="64.3">−0.1</text>
<text x="143.9" y="64.3">-</text>
<text x="157.6" y="64.3">0.8</text>
<text x="174.6" y="64.3">-</text>
<text x="183.6" y="64.3">ns</text>
<text x="18.4" y="69.6">f</text>
<text x="33.2" y="69.6">maximum</text>
<text x="56.3" y="69.6">nCP; see Fig. 5</text>
<text x="33.2" y="73.4">frequency</text>
<text x="61.3" y="75">V</text>
<text x="67.7" y="75">= 1.65 to 1.95 V</text>
<text x="111.1" y="75">150</text>
<text x="126.5" y="75">275</text>
<text x="143.9" y="75">-</text>
<text x="157.2" y="75">150</text>
<text x="174.6" y="75">-</text>
<text x="183.6" y="75">MHz</text>
<text x="61.3" y="80.3">V</text>
<text x="67.7" y="80.3">= 2.3 to 2.7 V</text>
<text x="111.1" y="80.3">200</text>
<text x="126.5" y="80.3">325</text>
<text x="143.9" y="80.3">-</text>
<text x="157.2" y="80.3">200</text>
<text x="174.6" y="80.3">-</text>
<text x="183.6" y="80.3">MHz</text>
<text x="61.3" y="85.7">V</text>
<text x="67.7" y="85.7">= 2.7 V</text>
<text x="111.1" y="85.7">250</text>
<text x="126.5" y="85.7">375</text>
<text x="143.9" y="85.7">-</text>
<text x="157.2" y="85.7">250</text>
<text x="174.6" y="85.7">-</text>
<text x="183.6" y="85.7">MHz</text>
<text x="61.3" y="91.1">V</text>
<text x="67.7" y="91.1">= 3.0 V to 3.6 V</text>
<text x="111.1" y="91.1">300</text>
<text x="126.5" y="91.1">425</text>
<text x="143.9" y="91.1">-</text>
<text x="157.2" y="91.1">300</text>
<text x="174.6" y="91.1">-</text>
<text x="183.6" y="91.1">MHz</text>
<text x="18.4" y="96.4">C</text>
<text x="33.2" y="96.4">power</text>
<text x="33.2" y="100.2">dissipation</text>
<text x="56.3" y="96.4">per buffer; V = GND to V</text>
<text x="56.3" y="100.2">V</text>
<text x="62.7" y="100.2">= 3.3 V</text>
<text x="94.9" y="96.4">;</text>
<text x="113.2" y="96.4">-</text>
<text x="127.4" y="96.4">35</text>
<text x="143.9" y="96.4">-</text>
<text x="159.3" y="96.4">-</text>
<text x="174.6" y="96.4">-</text>
<text x="183.6" y="96.4">pF</text>
<text x="33.2" y="104">capacitance</text>
<text x="31.4" y="253.5">Measurement points are given in Table 8.</text>
<text x="31.4" y="257.9">The shaded areas indicate when the input is permitted to change for predictable output performance.</text>
</g>
<text font-size="3.2" fill="#00f" x="102.2" y="96.4">[3]</text>
<g font-size="3.2" fill="#036f7b">
<text x="18.4" y="263.5">Fig. 5.</text>
<text x="31.4" y="263.5">Clock pulse (nCP) to output (nQ, nQ) propagation delays, nCP pulse width, the nD to nCP set-up times,</text>
<text x="31.4" y="267.3">the nCP to nD hold times and maximum frequency</text>
</g>
<g font-size="2.8">
<text x="17.6" y="111.9">[1]</text>
<text x="24" y="111.9">Typical values are measured at T</text>
<text x="70.5" y="111.9">= 25 °C.</text>
<text x="24" y="115.8">Typical values are measured at V</text>
<text x="24" y="119.8">Typical values are measured at V</text>
<text x="69.6" y="115.8">= 1.8 V for V</text>
<text x="69.6" y="119.8">= 2.5 V for V</text>
<text x="89.2" y="115.8">= 1.65 V to 1.95 V.</text>
<text x="89.2" y="119.8">= 2.3 V to 2.7 V.</text>
<text x="24" y="123.7">Typical values are measured at V</text>
<text x="69.6" y="123.7">= 3.3 V for V</text>
<text x="89.2" y="123.7">= 3.0 V to 3.6 V</text>
<text x="17.6" y="127.1">[2]</text>
<text x="17.6" y="130.5">[3]</text>
<text x="24" y="127.1">t</text>
<text x="24" y="130.5">C</text>
<text x="28" y="127.1">is the same as t</text>
<text x="29.8" y="130.5">is used to determine the dynamic power dissipation (P</text>
<text x="52.6" y="127.1">and t</text>
<text x="63" y="127.1">.</text>
<text x="99.7" y="130.5">in μW).</text>
<text x="24" y="134.4">P</text>
<text x="28.2" y="134.4">= C</text>
<text x="36.4" y="134.4">× V</text>
<text x="46.5" y="134.4">× f × N + Σ (C × V</text>
<text x="76.2" y="134.4">× f ), where:</text>
<text x="24" y="138.4">f = input frequency in MHz; f = output frequency in MHz;</text>
<text x="24" y="142.3">N = total load switching outputs; C = output load capacitance in pF;</text>
<text x="24" y="146.3">V</text>
<text x="29.8" y="146.3">= supply voltage in V;</text>
<text x="24" y="150.2">Σ (C × V</text>
<text x="41.6" y="150.2">× f ) = sum of outputs.</text>
</g>
<g font-size="2.8" fill="#036f7b">
<text x="17.6" y="287.2">Product data sheet</text>
<text x="88" y="287.2">Rev. 8 — 5 February 2024</text>
<text x="185.3" y="287.2">7 / 15</text>
</g>
<g font-size="2.5">
<text x="71.3" y="170.6">V</text>
<text x="57.6" y="176.3">nD input</text>
<text x="85.1" y="176.3">V</text>
<text x="68.1" y="182.4">GND</text>
<text x="99" y="184.7">t</text>
<text x="137.5" y="184.7">t</text>
<text x="89.2" y="188.2">t</text>
<text x="113.4" y="191.8">1/f</text>
<text x="127.8" y="188.2">t</text>
<text x="71.3" y="194.4">V</text>
<text x="56" y="200.2">nCP input</text>
<text x="101.3" y="200.9">V</text>
<text x="68.1" y="206.4">GND</text>
<text x="105.7" y="208.3">t</text>
<text x="68.7" y="214.3">V</text>
<text x="98.6" y="211.7">t</text>
<text x="137.1" y="211.7">t</text>
<text x="56" y="219.9">nQ output</text>
<text x="105.6" y="220.2">V</text>
<text x="69.2" y="226.2">V</text>
<text x="68.7" y="229.9">V</text>
<text x="56" y="235.8">nQ output</text>
<text x="105.6" y="235.8">V</text>
<text x="69.2" y="241.9">V</text>
<text x="98.7" y="244.7">t</text>
<text x="137" y="244.7">t</text>
</g>
<g font-size="2.4">
<text x="19.3" y="43.4">h</text>
<text x="63.4" y="48.8">CC</text>
<text x="63.4" y="54.1">CC</text>
<text x="63.4" y="59.5">CC</text>
<text x="63.4" y="64.9">CC</text>
<text x="19.3" y="70.2">max</text>
<text x="63.4" y="75.6">CC</text>
<text x="63.4" y="81">CC</text>
<text x="63.4" y="86.3">CC</text>
<text x="63.4" y="91.7">CC</text>
<text x="20.7" y="97">PD</text>
<text x="58.4" y="100.9">CC</text>
<text x="73.6" y="97">I</text>
<text x="91.5" y="97">CC</text>
</g>
<g font-size="2.1">
<text x="65.6" y="112.4">amb</text>
<text x="65.7" y="116.4">CC</text>
<text x="85.3" y="116.4">CC</text>
<text x="65.7" y="120.3">CC</text>
<text x="65.7" y="124.3">CC</text>
<text x="85.3" y="120.3">CC</text>
<text x="85.3" y="124.3">CC</text>
<text x="24.8" y="127.6">pd</text>
<text x="26.1" y="131">PD</text>
<text x="47.7" y="127.6">PHL</text>
<text x="58.9" y="127.6">PLH</text>
<text x="97.4" y="131">D</text>
<text x="25.9" y="135">D</text>
<text x="32.7" y="135">PD</text>
<text x="40.7" y="135">CC</text>
<text x="44.6" y="133">2</text>
<text x="49.7" y="135">i</text>
<text x="64.2" y="135">L</text>
<text x="70.4" y="135">CC</text>
<text x="74.3" y="133">2</text>
<text x="79.4" y="135">o</text>
<text x="24.8" y="138.9">i</text>
<text x="59.7" y="138.9">o</text>
<text x="66.7" y="142.9">L</text>
<text x="25.9" y="146.8">CC</text>
<text x="39.6" y="148.8">2</text>
<text x="29.5" y="150.8">L</text>
<text x="35.8" y="150.8">CC</text>
<text x="44.8" y="150.8">o</text>
<text x="73" y="171">I</text>
<text x="86.7" y="176.9">M</text>
<text x="99.7" y="185.2">h</text>
<text x="138.2" y="185.2">h</text>
<text x="89.9" y="188.7">su</text>
<text x="128.4" y="188.7">su</text>
<text x="73" y="195">I</text>
<text x="116.2" y="192.3">max</text>
<text x="103" y="201.4">M</text>
<text x="106.4" y="208.7">W</text>
<text x="70.4" y="214.8">OH</text>
<text x="99.3" y="212.2">PHL</text>
<text x="137.8" y="212.2">PLH</text>
<text x="107.3" y="220.7">M</text>
<text x="70.8" y="226.7">OL</text>
<text x="70.4" y="230.4">OH</text>
<text x="107.3" y="236.3">M</text>
<text x="70.8" y="242.3">OL</text>
<text x="99.4" y="245.2">PLH</text>
<text x="137.7" y="245.2">PHL</text>
<text x="142.6" y="248.5">aaa-008840</text>
</g>
<g font-size="1.8">
<text x="17.6" y="282">74ALVC74</text>
<text x="77.2" y="282">All information provided in this document is subject to legal disclaimers.</text>
<text x="162.2" y="282">Nexperia B.V. 2024. All rights reserved</text>
</g>
<text font-size="1.4" x="160.6" y="281.6">©</text>
</g></defs>
<path d="M17.6 18.8h174.8M106.1 28.6h46v5.3h-46z" fill="none" stroke="#036f7b" stroke-width=".21"/>
<path d="M106.2 28.6h45.9v5.3h-45.9z" fill="#e6f1f2"/>
<path d="M152.1 28.6h30.7v5.3h-30.7z" fill="none" stroke="#036f7b" stroke-width=".21"/>
<path d="M152.2 28.6h30.6v5.3h-30.6z" fill="#e6f1f2"/>
<path d="M17.6 28.5v10.8h14.9v-10.7h-14.9" fill="none" stroke="#036f7b" stroke-width=".21"/>
<path d="M17.7 28.6h14.7v10.6h-14.7z" fill="#e6f1f2"/>
<path d="M32.5 28.6h23v10.7h-23z" fill="none" stroke="#036f7b" stroke-width=".21"/>
<path d="M32.5 28.6h22.9v10.6h-22.9z" fill="#e6f1f2"/>
<path d="M101.5 28.6h-46v10.7h46" fill="none" stroke="#036f7b" stroke-width=".21"/>
<path d="M55.5 28.6h46v10.6h-46z" fill="#e6f1f2"/>
<path d="M101.5 28.6h4.6v10.7h-4.6" fill="none" stroke="#036f7b" stroke-width=".21"/>
<g fill="#e6f1f2">
<path d="M101.5 28.6h4.5v10.6h-4.5z"/>
<path d="M106.2 34h15.2v5.2h-15.2z"/>
</g>
<path d="M106.1 33.9h15.3v5.4h-15.3z" fill="none" stroke="#036f7b" stroke-width=".21"/>
<path d="M121.5 34h15.2v5.2h-15.2z" fill="#e6f1f2"/>
<path d="M121.4 33.9h15.4v5.4h-15.4z" fill="none" stroke="#036f7b" stroke-width=".21"/>
<path d="M136.9 34h15.2v5.2h-15.2z" fill="#e6f1f2"/>
<path d="M136.8 33.9h15.3v5.4h-15.3z" fill="none" stroke="#036f7b" stroke-width=".21"/>
<path d="M152.2 34h15.2v5.2h-15.2z" fill="#e6f1f2"/>
<path d="M152.1 33.9h15.4v5.4h-15.4z" fill="none" stroke="#036f7b" stroke-width=".21"/>
<path d="M167.6 34h15.2v5.2h-15.2z" fill="#e6f1f2"/>
<path d="M192.4 28.5v10.8h-24.9v-5.4h15.3M192.4 28.6h-9.6v10.7" fill="none" stroke="#036f7b" stroke-width=".21"/>
<path d="M182.9 28.6h9.4v10.6h-9.4z" fill="#e6f1f2"/>
<g fill="none" stroke="#036f7b" stroke-width=".21">
<path d="M17.6 39.3h174.8M17.6 28.6v77.4M17.7 28.6h174.6M32.5 28.6v77.3M55.5 28.6v77.3M106.1 28.6v77.3M106.2 33.9h76.6M121.4 34v71.9M136.8 34v71.9M152.1 28.6v77.3M167.5 34v71.9M182.8 28.6v77.3"/>
<path d="M192.4 28.6v77.4M55.5 44.7h136.9M55.5 50h136.9M55.5 55.4h136.9M17.6 66.1h174.8M55.5 60.7h136.9M55.5 71.5h136.9M55.5 76.8h136.9M17.6 92.9h174.8M55.5 82.2h136.9M55.5 87.6h136.9M17.6 105.9h174.8"/>
<path d="M17.6 167.2h174.8M17.6 167.1v102.1M192.4 167.1v102.1M17.6 269.2h174.8"/>
</g>
<path d="M78.6 43.1h8M70.2 69.9h7.9" fill="none" stroke="#00f" stroke-width=".21"/>
<g fill="#cbcbcb">
<path d="M138.9 169.6h15.1v12h-11.1z"/>
<path d="M104.2 169.6h20.1l-4 12h-20z"/>
<path d="M74.4 169.6h7.3l4 12h-11.3z"/>
</g>
<path d="M74.4 169.6h7.3l4 12M154 169.6h-49.8l-3.9 12M74.4 181.6h45.9l4-12h14.6l4 12h11.1M154 193.6h-15.8l-4 12h-15.7l-4-12h-14.9l-4 12h-21.2M74.4 213.4h27.8l4 11.9h34.4l4-11.9h9.4M74.4 241h27.8l4-12h34.4l4 12h9.4" fill="none" stroke="#000" stroke-width=".38"/>
<g fill="none" stroke="#000" stroke-width=".21">
<path d="M82.9 175.6h1.8M83.8 173.2v15.2M101.4 175.6h1.7M102.2 173.2v11.5M121.5 175.6h1.7M122.3 173.2v15.2M140 175.6h1.8M140.9 173.2v11.5M74.4 193.6h24.7M85 187.7h3.6M92.9 187.6h3.6M94.7 184h1.8"/>
<path d="M96.7 199.6h1.8M97.6 183.4v61.1M98.7 191h14.2M103.4 184h1.8M115.6 199.6h1.7M116.5 197.2v11.1M121 191h14M123.6 187.7h3.5M131.4 187.6h3.6M133.2 184h1.8M135.3 199.6h1.7M136.1 183.4v61.1"/>
<path d="M142 184h1.8M94.7 210.9h1.8M98.7 207.6h6.5M103.3 219.3h1.7M104.2 210.2v11.6M105.3 210.9h1.8M109.1 207.6h6.2M133.2 210.9h1.8M141.8 219.3h1.8M142.7 210.2v11.6M143.8 210.9h1.8M57.5 233.5h1.6"/>
<path d="M74.4 225.3h31.2M74.4 229h31.2M103.3 235h1.7M104.2 232.6v12.1M141.7 235h1.7M142.6 232.6v12.1M94.7 244h1.8M105.3 244h1.8M133.2 244h1.8M143.7 244h1.8"/>
</g>
<g fill="#000">
<path d="M83.9 187.7l1.4-.5v.9zM96.2 187.2l1.4 .4-1.4 .5zM96.2 183.6l1.4 .4-1.4 .5zM97.6 191l1.4-.4v.8zM102.2 184l1.5-.4v.9zM122.4 187.7l1.5-.5v.9zM134.7 187.2l1.4 .4-1.4 .5zM134.7 183.6l1.4 .4-1.4 .5zM134.7 190.6l1.4 .4-1.4 .4zM140.9 184l1.4-.4v.9zM96.2 210.5l1.4 .4-1.4 .4zM97.6 207.6l1.4-.4v.8z"/>
<path d="M104.2 210.9l1.4-.4v.8zM115 207.2l1.4 .4-1.4 .4zM134.7 210.5l1.4 .4-1.4 .4zM142.7 210.9l1.4-.4v.8zM96.2 243.6l1.4 .4-1.4 .4zM104.2 244l1.4-.4v.8zM134.7 243.6l1.4 .4-1.4 .4zM142.6 244l1.4-.4v.8z"/>
</g>
<path d="M78.3 253.8h10.3" fill="none" stroke="#00f" stroke-width=".21"/>
<path d="M17.6 167.3v101.8M17.7 167.2h174.6M192.4 167.3v101.8M17.7 269.2h174.6M83.2 261h2.5M17.6 282.6h174.8" fill="none" stroke="#036f7b" stroke-width=".21"/>
<use href="#words"/>
</svg>
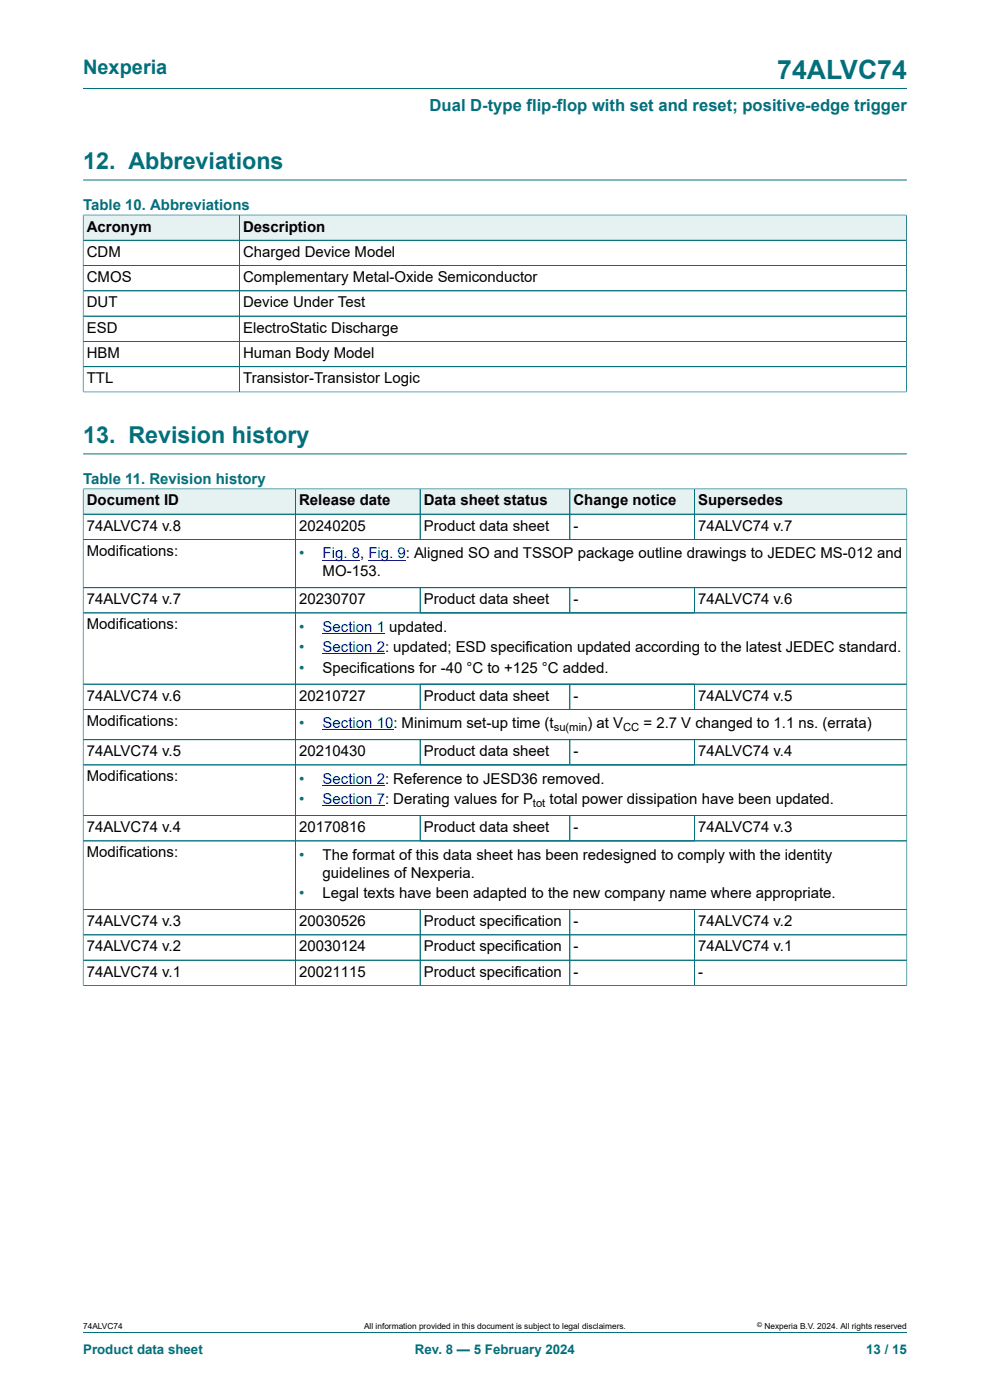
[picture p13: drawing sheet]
<svg xmlns="http://www.w3.org/2000/svg" width="210mm" height="297mm" viewBox="0 0 210 297" stroke-linecap="round" stroke-linejoin="round" font-family="sans-serif">
<defs><g id="words">
<text font-size="5.6" fill="#036f7b" x="164.9" y="16.8">74ALVC74</text>
<g font-size="4.9" fill="#036f7b">
<text x="17.6" y="35.9">12. Abbreviations</text>
<text x="17.6" y="94">13. Revision history</text>
</g>
<text font-size="4.2" fill="#036f7b" x="17.6" y="15.6">Nexperia</text>
<text font-size="3.5" fill="#036f7b" x="91.1" y="23.7">Dual D-type flip-flop with set and reset; positive-edge trigger</text>
<g font-size="3.2" fill="#036f7b">
<text x="17.6" y="44.5">Table 10. Abbreviations</text>
<text x="17.6" y="102.6">Table 11. Revision history</text>
<text x="63.4" y="118.5">•</text>
<text x="63.4" y="134.1">•</text>
<text x="63.4" y="138.4">•</text>
<text x="63.4" y="142.7">•</text>
<text x="63.4" y="154.5">•</text>
<text x="63.4" y="166.3">•</text>
<text x="63.4" y="170.6">•</text>
<text x="63.4" y="182.4">•</text>
<text x="63.4" y="190.6">•</text>
</g>
<g font-size="3.2">
<text x="18.4" y="49.1">Acronym</text>
<text x="51.6" y="49.1">Description</text>
<text x="18.4" y="54.5">CDM</text>
<text x="18.4" y="59.8">CMOS</text>
<text x="51.6" y="54.5">Charged Device Model</text>
<text x="51.6" y="59.8">Complementary Metal-Oxide Semiconductor</text>
<text x="18.4" y="65.2">DUT</text>
<text x="51.6" y="65.2">Device Under Test</text>
<text x="18.4" y="70.6">ESD</text>
<text x="51.6" y="70.6">ElectroStatic Discharge</text>
<text x="18.4" y="75.9">HBM</text>
<text x="51.6" y="75.9">Human Body Model</text>
<text x="18.4" y="81.3">TTL</text>
<text x="51.6" y="81.3">Transistor-Transistor Logic</text>
<text x="18.4" y="107.2">Document ID</text>
<text x="63.4" y="107.2">Release date</text>
<text x="89.9" y="107.2">Data sheet status</text>
<text x="121.7" y="107.2">Change notice</text>
<text x="148.1" y="107.2">Supersedes</text>
<text x="18.4" y="112.6">74ALVC74 v.8</text>
<text x="63.4" y="112.6">20240205</text>
<text x="89.9" y="112.6">Product data sheet</text>
<text x="121.7" y="112.6">-</text>
<text x="148.1" y="112.6">74ALVC74 v.7</text>
<text x="18.4" y="117.9">Modifications:</text>
<text x="68.4" y="122.3">MO-153.</text>
<text x="18.4" y="128.2">74ALVC74 v.7</text>
<text x="63.4" y="128.2">20230707</text>
<text x="89.9" y="128.2">Product data sheet</text>
<text x="121.7" y="128.2">-</text>
<text x="148.1" y="128.2">74ALVC74 v.6</text>
<text x="18.4" y="133.5">Modifications:</text>
<text x="68.4" y="142.7">Specifications for -40 °C to +125 °C added.</text>
<text x="18.4" y="148.6">74ALVC74 v.6</text>
<text x="63.4" y="148.6">20210727</text>
<text x="89.9" y="148.6">Product data sheet</text>
<text x="121.7" y="148.6">-</text>
<text x="148.1" y="148.6">74ALVC74 v.5</text>
<text x="18.4" y="154">Modifications:</text>
<text x="124.6" y="154.5">) at V</text>
<text x="136.5" y="154.5">= 2.7 V changed to 1.1 ns. (errata)</text>
<text x="18.4" y="160.4">74ALVC74 v.5</text>
<text x="63.4" y="160.4">20210430</text>
<text x="89.9" y="160.4">Product data sheet</text>
<text x="121.7" y="160.4">-</text>
<text x="148.1" y="160.4">74ALVC74 v.4</text>
<text x="18.4" y="165.8">Modifications:</text>
<text x="116.6" y="170.6">total power dissipation have been updated.</text>
<text x="18.4" y="176.5">74ALVC74 v.4</text>
<text x="63.4" y="176.5">20170816</text>
<text x="89.9" y="176.5">Product data sheet</text>
<text x="121.7" y="176.5">-</text>
<text x="148.1" y="176.5">74ALVC74 v.3</text>
<text x="18.4" y="181.9">Modifications:</text>
<text x="68.4" y="182.4">The format of this data sheet has been redesigned to comply with the identity</text>
<text x="68.4" y="186.2">guidelines of Nexperia.</text>
<text x="68.4" y="190.6">Legal texts have been adapted to the new company name where appropriate.</text>
<text x="18.4" y="196.5">74ALVC74 v.3</text>
<text x="63.4" y="196.5">20030526</text>
<text x="89.9" y="196.5">Product specification</text>
<text x="121.7" y="196.5">-</text>
<text x="148.1" y="196.5">74ALVC74 v.2</text>
<text x="18.4" y="201.8">74ALVC74 v.2</text>
<text x="63.4" y="201.8">20030124</text>
<text x="89.9" y="201.8">Product specification</text>
<text x="121.7" y="201.8">-</text>
<text x="148.1" y="201.8">74ALVC74 v.1</text>
<text x="18.4" y="207.2">74ALVC74 v.1</text>
<text x="63.4" y="207.2">20021115</text>
<text x="89.9" y="207.2">Product specification</text>
<text x="121.7" y="207.2">-</text>
<text x="148.1" y="207.2">-</text>
</g>
<g font-size="3.2" fill="#00f">
<text x="68.4" y="118.5">Fig. 8, Fig. 9: Aligned SO and TSSOP package outline drawings to JEDEC MS-012 and</text>
<text x="68.4" y="134.1">Section 1 updated.</text>
<text x="68.4" y="138.4">Section 2: updated; ESD specification updated according to the latest JEDEC standard.</text>
<text x="68.4" y="154.5">Section 10: Minimum set-up time (t</text>
<text x="68.4" y="166.3">Section 2: Reference to JESD36 removed.</text>
<text x="68.4" y="170.6">Section 7: Derating values for P</text>
</g>
<g font-size="2.8" fill="#036f7b">
<text x="17.6" y="287.2">Product data sheet</text>
<text x="88" y="287.2">Rev. 8 — 5 February 2024</text>
<text x="183.7" y="287.2">13 / 15</text>
</g>
<g font-size="2.4">
<text x="117.5" y="155.1">su(min</text>
<text x="132.2" y="155.1">CC</text>
<text x="113.1" y="171.3">tot</text>
</g>
<g font-size="1.8">
<text x="17.6" y="282">74ALVC74</text>
<text x="77.2" y="282">All information provided in this document is subject to legal disclaimers.</text>
<text x="162.2" y="282">Nexperia B.V. 2024. All rights reserved</text>
</g>
<text font-size="1.4" x="160.6" y="281.6">©</text>
</g></defs>
<path d="M17.6 18.8h174.8M17.6 38.2h174.8" fill="none" stroke="#036f7b" stroke-width=".21"/>
<path d="M17.7 45.7h33v5.2h-33z" fill="#e6f1f2"/>
<path d="M17.6 45.5v5.5h33.2v-5.4h-33.2" fill="none" stroke="#036f7b" stroke-width=".21"/>
<path d="M50.9 45.7h141.3v5.2h-141.3z" fill="#e6f1f2"/>
<path d="M17.6 51h174.7M17.6 56.3h174.7M17.6 45.7v37.5M17.7 45.6h174.6M50.8 45.6v37.5M192.3 45.5v37.7M17.6 61.7h174.7M17.6 67.1h174.7M17.6 72.4h174.7M17.6 77.8h174.7M17.6 83.1h174.7M17.6 96.3h174.8" fill="none" stroke="#036f7b" stroke-width=".21"/>
<path d="M17.7 103.8h44.9v5.2h-44.9z" fill="#e6f1f2"/>
<path d="M17.6 103.6v5.5h45.1v-5.4h-45.1" fill="none" stroke="#036f7b" stroke-width=".21"/>
<path d="M62.7 103.8h26.4v5.2h-26.4z" fill="#e6f1f2"/>
<path d="M62.7 103.7h26.4v5.4h-26.4z" fill="none" stroke="#036f7b" stroke-width=".21"/>
<path d="M89.2 103.8h31.6v5.2h-31.6z" fill="#e6f1f2"/>
<path d="M89.1 103.7h31.8v5.4h-31.8z" fill="none" stroke="#036f7b" stroke-width=".21"/>
<path d="M120.9 103.8h26.4v5.2h-26.4z" fill="#e6f1f2"/>
<path d="M120.9 103.7h26.4v5.4h-26.4z" fill="none" stroke="#036f7b" stroke-width=".21"/>
<path d="M147.4 103.8h44.9v5.2h-44.9z" fill="#e6f1f2"/>
<path d="M17.6 114.4h174.8M62.7 109.1v36M89.1 109.1v5.3M120.9 109.1v5.3M192.4 103.6v41.5h-174.8v-36h174.8M192.4 103.7h-45.1v10.7M17.6 124.7h174.8M17.6 130h174.8M89.1 124.7v5.3M120.9 124.7v5.3M147.3 124.7v5.3" fill="none" stroke="#036f7b" stroke-width=".21"/>
<path d="M68.4 118.8h8M78.1 118.8h8M68.4 134.4h11.5" fill="none" stroke="#00f" stroke-width=".21"/>
<path d="M79.9 134.4h1.8z" fill="#00f"/>
<path d="M68.4 138.7h11.5" fill="none" stroke="#00f" stroke-width=".21"/>
<path d="M79.9 138.7l1.8 .1z" fill="#00f"/>
<path d="M17.6 150.5h174.8M17.6 156.9h174.8M17.6 145.1h174.8v27.9h-174.8zM62.7 145.1v27.9M89.1 145.1v5.4M89.1 156.9v5.4M120.9 145.1v5.4M120.9 156.9v5.4M147.3 145.1v5.4M147.3 156.9v5.4M17.6 162.3h174.8" fill="none" stroke="#036f7b" stroke-width=".21"/>
<path d="M68.4 154.9h15M68.4 166.6h11.5" fill="none" stroke="#00f" stroke-width=".21"/>
<path d="M79.9 166.6l1.8 .1z" fill="#00f"/>
<path d="M68.4 171h11.5" fill="none" stroke="#00f" stroke-width=".21"/>
<path d="M79.9 170.9l1.8 .1z" fill="#00f"/>
<g fill="none" stroke="#036f7b" stroke-width=".21">
<path d="M17.6 103.8v105.3M17.7 109.1h174.6M17.7 114.4h174.6M17.7 103.7h174.6M62.7 103.8v105.3M89.1 103.8v10.6M120.9 103.8v10.6M147.3 103.8v10.6M192.4 103.8v105.3M17.7 124.7h174.6M17.7 130h174.6M89.1 124.7v5.3"/>
<path d="M120.9 124.7v5.3M147.3 124.7v5.3M17.7 145.1h174.6M17.7 150.5h174.6M17.7 156.9h174.6M89.1 145.2v5.2M89.1 157v5.2M120.9 145.2v5.2M120.9 157v5.2M147.3 145.2v5.2M147.3 157v5.2M17.6 178.4h174.8"/>
<path d="M17.6 173h174.8M17.7 162.3h174.6M89.1 173v5.4M120.9 173v5.4M147.3 173v5.4M17.6 193h174.8M17.6 198.3h174.8M89.1 193v16.1M120.9 193v16.1M147.3 193v16.1M17.6 209.1h174.8M17.6 203.7h174.8"/>
<path d="M17.6 282.6h174.8"/>
</g>
<use href="#words"/>
</svg>
